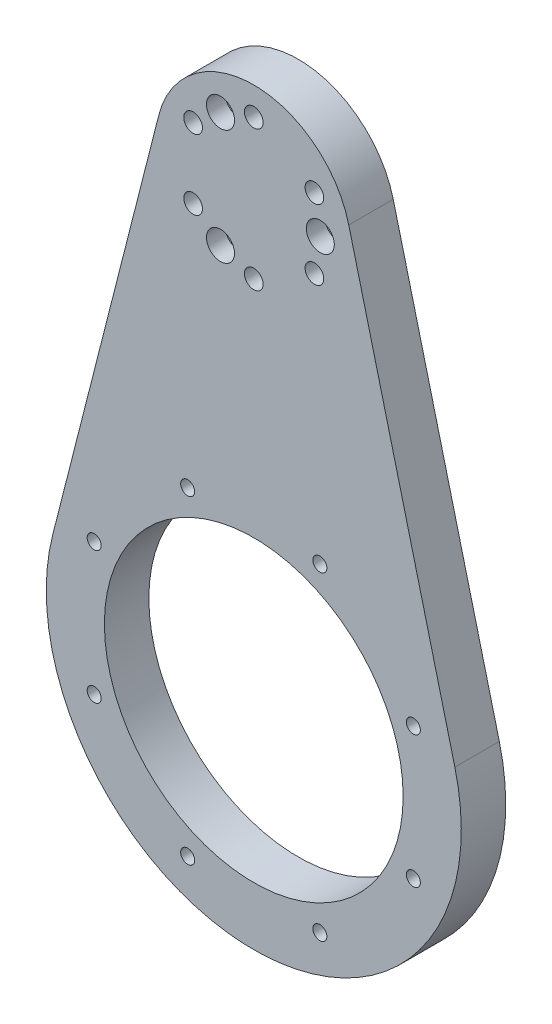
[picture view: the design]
ISO-10303-21;
HEADER;
FILE_DESCRIPTION(('STEP AP214'),'2;1');
FILE_NAME('part.step','',(''),(''),'','','');
FILE_SCHEMA(('AUTOMOTIVE_DESIGN { 1 0 10303 214 1 1 1 1 }'));
ENDSEC;
DATA;
#1=APPLICATION_CONTEXT('core data for automotive mechanical design processes');
#2=APPLICATION_PROTOCOL_DEFINITION('international standard','automotive_design',2000,#1);
#3=PRODUCT_CONTEXT('',#1,'mechanical');
#4=PRODUCT('Part','Part','',(#3));
#5=PRODUCT_RELATED_PRODUCT_CATEGORY('part','',(#4));
#6=PRODUCT_DEFINITION_FORMATION('','',#4);
#7=PRODUCT_DEFINITION_CONTEXT('part definition',#1,'design');
#8=PRODUCT_DEFINITION('design','',#6,#7);
#9=PRODUCT_DEFINITION_SHAPE('','',#8);
#10=(LENGTH_UNIT() NAMED_UNIT(*) SI_UNIT(.MILLI.,.METRE.));
#11=(NAMED_UNIT(*) PLANE_ANGLE_UNIT() SI_UNIT($,.RADIAN.));
#12=(NAMED_UNIT(*) SI_UNIT($,.STERADIAN.) SOLID_ANGLE_UNIT());
#13=UNCERTAINTY_MEASURE_WITH_UNIT(LENGTH_MEASURE(1.E-05),#10,'distance_accuracy_value','');
#14=(GEOMETRIC_REPRESENTATION_CONTEXT(3) GLOBAL_UNCERTAINTY_ASSIGNED_CONTEXT((#13)) GLOBAL_UNIT_ASSIGNED_CONTEXT((#10,
#11,#12)) REPRESENTATION_CONTEXT('',''));
#15=CARTESIAN_POINT('',(0.,0.,0.));
#16=DIRECTION('',(0.,0.,1.));
#17=DIRECTION('',(1.,0.,0.));
#18=AXIS2_PLACEMENT_3D('',#15,#16,#17);
#19=CARTESIAN_POINT('',(0.,-95.,9.525));
#20=DIRECTION('',(0.,0.,1.));
#21=DIRECTION('',(1.,0.,0.));
#22=AXIS2_PLACEMENT_3D('',#19,#20,#21);
#23=PLANE('',#22);
#24=CARTESIAN_POINT('',(14.25,-1.50920942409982E-13,9.525));
#25=DIRECTION('',(0.,0.,1.));
#26=DIRECTION('',(1.,0.,0.));
#27=AXIS2_PLACEMENT_3D('',#24,#25,#26);
#28=CIRCLE('',#27,3.);
#29=CARTESIAN_POINT('',(11.25,-1.50920942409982E-13,9.525));
#30=VERTEX_POINT('',#29);
#31=EDGE_CURVE('E155',#30,#30,#28,.T.);
#32=ORIENTED_EDGE('',*,*,#31,.F.);
#33=EDGE_LOOP('',(#32));
#34=FACE_BOUND('',#33,.T.);
#35=CARTESIAN_POINT('',(-12.9903810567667,-7.49999999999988,9.525));
#36=DIRECTION('',(0.,0.,1.));
#37=DIRECTION('',(1.,0.,0.));
#38=AXIS2_PLACEMENT_3D('',#35,#36,#37);
#39=CIRCLE('',#38,2.);
#40=CARTESIAN_POINT('',(-14.9903810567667,-7.49999999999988,9.525));
#41=VERTEX_POINT('',#40);
#42=EDGE_CURVE('E168',#41,#41,#39,.T.);
#43=ORIENTED_EDGE('',*,*,#42,.F.);
#44=EDGE_LOOP('',(#43));
#45=FACE_BOUND('',#44,.T.);
#46=CARTESIAN_POINT('',(12.9903810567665,-7.50000000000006,9.525));
#47=DIRECTION('',(0.,0.,1.));
#48=DIRECTION('',(1.,0.,0.));
#49=AXIS2_PLACEMENT_3D('',#46,#47,#48);
#50=CIRCLE('',#49,2.);
#51=CARTESIAN_POINT('',(10.9903810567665,-7.50000000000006,9.525));
#52=VERTEX_POINT('',#51);
#53=EDGE_CURVE('E188',#52,#52,#50,.T.);
#54=ORIENTED_EDGE('',*,*,#53,.F.);
#55=EDGE_LOOP('',(#54));
#56=FACE_BOUND('',#55,.T.);
#57=CARTESIAN_POINT('',(-7.12499999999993,12.3408620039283,9.525));
#58=DIRECTION('',(0.,0.,1.));
#59=DIRECTION('',(1.,0.,0.));
#60=AXIS2_PLACEMENT_3D('',#57,#58,#59);
#61=CIRCLE('',#60,3.);
#62=CARTESIAN_POINT('',(-10.1249999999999,12.3408620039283,9.525));
#63=VERTEX_POINT('',#62);
#64=EDGE_CURVE('E196',#63,#63,#61,.T.);
#65=ORIENTED_EDGE('',*,*,#64,.F.);
#66=EDGE_LOOP('',(#65));
#67=FACE_BOUND('',#66,.T.);
#68=CARTESIAN_POINT('',(34.1835427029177,-109.159286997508,9.525));
#69=DIRECTION('',(0.,0.,1.));
#70=DIRECTION('',(1.,0.,0.));
#71=AXIS2_PLACEMENT_3D('',#68,#69,#70);
#72=CIRCLE('',#71,1.49999999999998);
#73=CARTESIAN_POINT('',(32.6835427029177,-109.159286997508,9.525));
#74=VERTEX_POINT('',#73);
#75=EDGE_CURVE('E212',#74,#74,#72,.T.);
#76=ORIENTED_EDGE('',*,*,#75,.F.);
#77=EDGE_LOOP('',(#76));
#78=FACE_BOUND('',#77,.T.);
#79=CARTESIAN_POINT('',(14.1592869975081,-60.8164572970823,9.525));
#80=DIRECTION('',(0.,0.,1.));
#81=DIRECTION('',(1.,0.,0.));
#82=AXIS2_PLACEMENT_3D('',#79,#80,#81);
#83=CIRCLE('',#82,1.5);
#84=CARTESIAN_POINT('',(12.6592869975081,-60.8164572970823,9.525));
#85=VERTEX_POINT('',#84);
#86=EDGE_CURVE('E226',#85,#85,#83,.T.);
#87=ORIENTED_EDGE('',*,*,#86,.F.);
#88=EDGE_LOOP('',(#87));
#89=FACE_BOUND('',#88,.T.);
#90=CARTESIAN_POINT('',(-34.1835427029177,-80.8407130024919,9.525));
#91=DIRECTION('',(0.,0.,1.));
#92=DIRECTION('',(1.,0.,0.));
#93=AXIS2_PLACEMENT_3D('',#90,#91,#92);
#94=CIRCLE('',#93,1.5);
#95=CARTESIAN_POINT('',(-35.6835427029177,-80.8407130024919,9.525));
#96=VERTEX_POINT('',#95);
#97=EDGE_CURVE('E248',#96,#96,#94,.T.);
#98=ORIENTED_EDGE('',*,*,#97,.F.);
#99=EDGE_LOOP('',(#98));
#100=FACE_BOUND('',#99,.T.);
#101=CARTESIAN_POINT('',(0.,15.,9.525));
#102=DIRECTION('',(0.,0.,1.));
#103=DIRECTION('',(1.,0.,0.));
#104=AXIS2_PLACEMENT_3D('',#101,#102,#103);
#105=CIRCLE('',#104,2.);
#106=CARTESIAN_POINT('',(-2.,15.,9.525));
#107=VERTEX_POINT('',#106);
#108=EDGE_CURVE('E265',#107,#107,#105,.T.);
#109=ORIENTED_EDGE('',*,*,#108,.F.);
#110=EDGE_LOOP('',(#109));
#111=FACE_BOUND('',#110,.T.);
#112=CARTESIAN_POINT('',(0.,-95.,9.525));
#113=DIRECTION('',(0.,0.,1.));
#114=DIRECTION('',(1.,0.,0.));
#115=AXIS2_PLACEMENT_3D('',#112,#113,#114);
#116=CIRCLE('',#115,32.);
#117=CARTESIAN_POINT('',(-32.,-95.,9.525));
#118=VERTEX_POINT('',#117);
#119=EDGE_CURVE('E125',#118,#118,#116,.T.);
#120=ORIENTED_EDGE('',*,*,#119,.F.);
#121=EDGE_LOOP('',(#120));
#122=FACE_BOUND('',#121,.T.);
#123=CARTESIAN_POINT('',(0.,-95.,9.525));
#124=DIRECTION('',(0.,0.,1.));
#125=DIRECTION('',(1.,0.,0.));
#126=AXIS2_PLACEMENT_3D('',#123,#124,#125);
#127=CIRCLE('',#126,44.45);
#128=CARTESIAN_POINT('',(-43.074526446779,-84.0278684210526,9.525));
#129=VERTEX_POINT('',#128);
#130=CARTESIAN_POINT('',(43.074526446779,-84.0278684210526,9.525));
#131=VERTEX_POINT('',#130);
#132=EDGE_CURVE('E97',#129,#131,#127,.T.);
#133=ORIENTED_EDGE('',*,*,#132,.T.);
#134=DIRECTION('',(-0.246842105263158,0.969055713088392,0.));
#135=VECTOR('',#134,1.);
#136=CARTESIAN_POINT('',(43.074526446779,-84.0278684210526,9.525));
#137=LINE('',#136,#135);
#138=CARTESIAN_POINT('',(20.3501699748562,5.18368421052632,9.525));
#139=VERTEX_POINT('',#138);
#140=EDGE_CURVE('E94',#131,#139,#137,.T.);
#141=ORIENTED_EDGE('',*,*,#140,.T.);
#142=CARTESIAN_POINT('',(0.,0.,9.525));
#143=DIRECTION('',(0.,0.,1.));
#144=DIRECTION('',(1.,0.,0.));
#145=AXIS2_PLACEMENT_3D('',#142,#143,#144);
#146=CIRCLE('',#145,21.);
#147=CARTESIAN_POINT('',(-20.3501699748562,5.18368421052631,9.525));
#148=VERTEX_POINT('',#147);
#149=EDGE_CURVE('E100',#139,#148,#146,.T.);
#150=ORIENTED_EDGE('',*,*,#149,.T.);
#151=DIRECTION('',(-0.246842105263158,-0.969055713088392,0.));
#152=VECTOR('',#151,1.);
#153=CARTESIAN_POINT('',(-43.074526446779,-84.0278684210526,9.525));
#154=LINE('',#153,#152);
#155=EDGE_CURVE('E62',#148,#129,#154,.T.);
#156=ORIENTED_EDGE('',*,*,#155,.T.);
#157=EDGE_LOOP('',(#133,#141,#150,#156));
#158=FACE_BOUND('',#157,.T.);
#159=CARTESIAN_POINT('',(-14.1592869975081,-129.183542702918,9.525));
#160=DIRECTION('',(0.,0.,1.));
#161=DIRECTION('',(1.,0.,0.));
#162=AXIS2_PLACEMENT_3D('',#159,#160,#161);
#163=CIRCLE('',#162,1.5);
#164=CARTESIAN_POINT('',(-15.6592869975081,-129.183542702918,9.525));
#165=VERTEX_POINT('',#164);
#166=EDGE_CURVE('E269',#165,#165,#163,.T.);
#167=ORIENTED_EDGE('',*,*,#166,.F.);
#168=EDGE_LOOP('',(#167));
#169=FACE_BOUND('',#168,.T.);
#170=CARTESIAN_POINT('',(-34.1835427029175,-109.159286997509,9.525));
#171=DIRECTION('',(0.,0.,1.));
#172=DIRECTION('',(1.,0.,0.));
#173=AXIS2_PLACEMENT_3D('',#170,#171,#172);
#174=CIRCLE('',#173,1.5);
#175=CARTESIAN_POINT('',(-35.6835427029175,-109.159286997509,9.525));
#176=VERTEX_POINT('',#175);
#177=EDGE_CURVE('E255',#176,#176,#174,.T.);
#178=ORIENTED_EDGE('',*,*,#177,.F.);
#179=EDGE_LOOP('',(#178));
#180=FACE_BOUND('',#179,.T.);
#181=CARTESIAN_POINT('',(-14.1592869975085,-60.8164572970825,9.525));
#182=DIRECTION('',(0.,0.,1.));
#183=DIRECTION('',(1.,0.,0.));
#184=AXIS2_PLACEMENT_3D('',#181,#182,#183);
#185=CIRCLE('',#184,1.5);
#186=CARTESIAN_POINT('',(-15.6592869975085,-60.8164572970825,9.525));
#187=VERTEX_POINT('',#186);
#188=EDGE_CURVE('E236',#187,#187,#185,.T.);
#189=ORIENTED_EDGE('',*,*,#188,.F.);
#190=EDGE_LOOP('',(#189));
#191=FACE_BOUND('',#190,.T.);
#192=CARTESIAN_POINT('',(34.1835427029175,-80.8407130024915,9.525));
#193=DIRECTION('',(0.,0.,1.));
#194=DIRECTION('',(1.,0.,0.));
#195=AXIS2_PLACEMENT_3D('',#192,#193,#194);
#196=CIRCLE('',#195,1.5);
#197=CARTESIAN_POINT('',(32.6835427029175,-80.8407130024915,9.525));
#198=VERTEX_POINT('',#197);
#199=EDGE_CURVE('E225',#198,#198,#196,.T.);
#200=ORIENTED_EDGE('',*,*,#199,.F.);
#201=EDGE_LOOP('',(#200));
#202=FACE_BOUND('',#201,.T.);
#203=CARTESIAN_POINT('',(14.1592869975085,-129.183542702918,9.525));
#204=DIRECTION('',(0.,0.,1.));
#205=DIRECTION('',(1.,0.,0.));
#206=AXIS2_PLACEMENT_3D('',#203,#204,#205);
#207=CIRCLE('',#206,1.49999999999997);
#208=CARTESIAN_POINT('',(12.6592869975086,-129.183542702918,9.525));
#209=VERTEX_POINT('',#208);
#210=EDGE_CURVE('E206',#209,#209,#207,.T.);
#211=ORIENTED_EDGE('',*,*,#210,.F.);
#212=EDGE_LOOP('',(#211));
#213=FACE_BOUND('',#212,.T.);
#214=CARTESIAN_POINT('',(12.9903810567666,7.49999999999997,9.525));
#215=DIRECTION('',(0.,0.,1.));
#216=DIRECTION('',(1.,0.,0.));
#217=AXIS2_PLACEMENT_3D('',#214,#215,#216);
#218=CIRCLE('',#217,2.);
#219=CARTESIAN_POINT('',(10.9903810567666,7.49999999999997,9.525));
#220=VERTEX_POINT('',#219);
#221=EDGE_CURVE('E192',#220,#220,#218,.T.);
#222=ORIENTED_EDGE('',*,*,#221,.F.);
#223=EDGE_LOOP('',(#222));
#224=FACE_BOUND('',#223,.T.);
#225=CARTESIAN_POINT('',(-1.04744440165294E-13,-15.,9.525));
#226=DIRECTION('',(0.,0.,1.));
#227=DIRECTION('',(1.,0.,0.));
#228=AXIS2_PLACEMENT_3D('',#225,#226,#227);
#229=CIRCLE('',#228,2.);
#230=CARTESIAN_POINT('',(-2.0000000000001,-15.,9.525));
#231=VERTEX_POINT('',#230);
#232=EDGE_CURVE('E176',#231,#231,#229,.T.);
#233=ORIENTED_EDGE('',*,*,#232,.F.);
#234=EDGE_LOOP('',(#233));
#235=FACE_BOUND('',#234,.T.);
#236=CARTESIAN_POINT('',(-12.9903810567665,7.50000000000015,9.525));
#237=DIRECTION('',(0.,0.,1.));
#238=DIRECTION('',(1.,0.,0.));
#239=AXIS2_PLACEMENT_3D('',#236,#237,#238);
#240=CIRCLE('',#239,2.);
#241=CARTESIAN_POINT('',(-14.9903810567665,7.50000000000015,9.525));
#242=VERTEX_POINT('',#241);
#243=EDGE_CURVE('E161',#242,#242,#240,.T.);
#244=ORIENTED_EDGE('',*,*,#243,.F.);
#245=EDGE_LOOP('',(#244));
#246=FACE_BOUND('',#245,.T.);
#247=CARTESIAN_POINT('',(-7.12500000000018,-12.3408620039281,9.525));
#248=DIRECTION('',(0.,0.,1.));
#249=DIRECTION('',(1.,0.,0.));
#250=AXIS2_PLACEMENT_3D('',#247,#248,#249);
#251=CIRCLE('',#250,3.);
#252=CARTESIAN_POINT('',(-10.1250000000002,-12.3408620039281,9.525));
#253=VERTEX_POINT('',#252);
#254=EDGE_CURVE('E156',#253,#253,#251,.T.);
#255=ORIENTED_EDGE('',*,*,#254,.F.);
#256=EDGE_LOOP('',(#255));
#257=FACE_BOUND('',#256,.T.);
#258=ADVANCED_FACE('F44',(#34,#45,#56,#67,#78,#89,#100,#111,#122,#158,#169,#180,#191,#202,#213,
#224,#235,#246,#257),#23,.T.);
#259=CARTESIAN_POINT('',(0.,-95.,0.));
#260=DIRECTION('',(0.,0.,1.));
#261=DIRECTION('',(1.,0.,0.));
#262=AXIS2_PLACEMENT_3D('',#259,#260,#261);
#263=PLANE('',#262);
#264=CARTESIAN_POINT('',(0.,-95.,0.));
#265=DIRECTION('',(0.,0.,1.));
#266=DIRECTION('',(1.,0.,0.));
#267=AXIS2_PLACEMENT_3D('',#264,#265,#266);
#268=CIRCLE('',#267,44.45);
#269=CARTESIAN_POINT('',(-43.074526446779,-84.0278684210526,0.));
#270=VERTEX_POINT('',#269);
#271=CARTESIAN_POINT('',(43.074526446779,-84.0278684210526,0.));
#272=VERTEX_POINT('',#271);
#273=EDGE_CURVE('E117',#270,#272,#268,.T.);
#274=ORIENTED_EDGE('',*,*,#273,.F.);
#275=DIRECTION('',(-0.246842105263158,-0.969055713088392,0.));
#276=VECTOR('',#275,1.);
#277=CARTESIAN_POINT('',(-43.074526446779,-84.0278684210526,0.));
#278=LINE('',#277,#276);
#279=CARTESIAN_POINT('',(-20.3501699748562,5.18368421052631,0.));
#280=VERTEX_POINT('',#279);
#281=EDGE_CURVE('E88',#280,#270,#278,.T.);
#282=ORIENTED_EDGE('',*,*,#281,.F.);
#283=CARTESIAN_POINT('',(0.,0.,0.));
#284=DIRECTION('',(0.,0.,1.));
#285=DIRECTION('',(1.,0.,0.));
#286=AXIS2_PLACEMENT_3D('',#283,#284,#285);
#287=CIRCLE('',#286,21.);
#288=CARTESIAN_POINT('',(20.3501699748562,5.18368421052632,0.));
#289=VERTEX_POINT('',#288);
#290=EDGE_CURVE('E76',#289,#280,#287,.T.);
#291=ORIENTED_EDGE('',*,*,#290,.F.);
#292=DIRECTION('',(-0.246842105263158,0.969055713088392,0.));
#293=VECTOR('',#292,1.);
#294=CARTESIAN_POINT('',(43.074526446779,-84.0278684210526,0.));
#295=LINE('',#294,#293);
#296=EDGE_CURVE('E104',#272,#289,#295,.T.);
#297=ORIENTED_EDGE('',*,*,#296,.F.);
#298=EDGE_LOOP('',(#274,#282,#291,#297));
#299=FACE_BOUND('',#298,.T.);
#300=CARTESIAN_POINT('',(0.,-95.,0.));
#301=DIRECTION('',(0.,0.,1.));
#302=DIRECTION('',(1.,0.,0.));
#303=AXIS2_PLACEMENT_3D('',#300,#301,#302);
#304=CIRCLE('',#303,32.);
#305=CARTESIAN_POINT('',(-32.,-95.,0.));
#306=VERTEX_POINT('',#305);
#307=EDGE_CURVE('E273',#306,#306,#304,.T.);
#308=ORIENTED_EDGE('',*,*,#307,.T.);
#309=EDGE_LOOP('',(#308));
#310=FACE_BOUND('',#309,.T.);
#311=CARTESIAN_POINT('',(-14.1592869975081,-129.183542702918,0.));
#312=DIRECTION('',(0.,0.,1.));
#313=DIRECTION('',(1.,0.,0.));
#314=AXIS2_PLACEMENT_3D('',#311,#312,#313);
#315=CIRCLE('',#314,1.5);
#316=CARTESIAN_POINT('',(-15.6592869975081,-129.183542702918,0.));
#317=VERTEX_POINT('',#316);
#318=EDGE_CURVE('E266',#317,#317,#315,.T.);
#319=ORIENTED_EDGE('',*,*,#318,.T.);
#320=EDGE_LOOP('',(#319));
#321=FACE_BOUND('',#320,.T.);
#322=CARTESIAN_POINT('',(0.,15.,0.));
#323=DIRECTION('',(0.,0.,1.));
#324=DIRECTION('',(1.,0.,0.));
#325=AXIS2_PLACEMENT_3D('',#322,#323,#324);
#326=CIRCLE('',#325,2.);
#327=CARTESIAN_POINT('',(-2.,15.,0.));
#328=VERTEX_POINT('',#327);
#329=EDGE_CURVE('E256',#328,#328,#326,.T.);
#330=ORIENTED_EDGE('',*,*,#329,.T.);
#331=EDGE_LOOP('',(#330));
#332=FACE_BOUND('',#331,.T.);
#333=CARTESIAN_POINT('',(-34.1835427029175,-109.159286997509,0.));
#334=DIRECTION('',(0.,0.,1.));
#335=DIRECTION('',(1.,0.,0.));
#336=AXIS2_PLACEMENT_3D('',#333,#334,#335);
#337=CIRCLE('',#336,1.5);
#338=CARTESIAN_POINT('',(-35.6835427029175,-109.159286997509,0.));
#339=VERTEX_POINT('',#338);
#340=EDGE_CURVE('E249',#339,#339,#337,.T.);
#341=ORIENTED_EDGE('',*,*,#340,.T.);
#342=EDGE_LOOP('',(#341));
#343=FACE_BOUND('',#342,.T.);
#344=CARTESIAN_POINT('',(-34.1835427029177,-80.8407130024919,0.));
#345=DIRECTION('',(0.,0.,1.));
#346=DIRECTION('',(1.,0.,0.));
#347=AXIS2_PLACEMENT_3D('',#344,#345,#346);
#348=CIRCLE('',#347,1.5);
#349=CARTESIAN_POINT('',(-35.6835427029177,-80.8407130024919,0.));
#350=VERTEX_POINT('',#349);
#351=EDGE_CURVE('E244',#350,#350,#348,.T.);
#352=ORIENTED_EDGE('',*,*,#351,.T.);
#353=EDGE_LOOP('',(#352));
#354=FACE_BOUND('',#353,.T.);
#355=CARTESIAN_POINT('',(-14.1592869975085,-60.8164572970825,0.));
#356=DIRECTION('',(0.,0.,1.));
#357=DIRECTION('',(1.,0.,0.));
#358=AXIS2_PLACEMENT_3D('',#355,#356,#357);
#359=CIRCLE('',#358,1.5);
#360=CARTESIAN_POINT('',(-15.6592869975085,-60.8164572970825,0.));
#361=VERTEX_POINT('',#360);
#362=EDGE_CURVE('E232',#361,#361,#359,.T.);
#363=ORIENTED_EDGE('',*,*,#362,.T.);
#364=EDGE_LOOP('',(#363));
#365=FACE_BOUND('',#364,.T.);
#366=CARTESIAN_POINT('',(14.1592869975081,-60.8164572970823,0.));
#367=DIRECTION('',(0.,0.,1.));
#368=DIRECTION('',(1.,0.,0.));
#369=AXIS2_PLACEMENT_3D('',#366,#367,#368);
#370=CIRCLE('',#369,1.5);
#371=CARTESIAN_POINT('',(12.6592869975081,-60.8164572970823,0.));
#372=VERTEX_POINT('',#371);
#373=EDGE_CURVE('E228',#372,#372,#370,.T.);
#374=ORIENTED_EDGE('',*,*,#373,.T.);
#375=EDGE_LOOP('',(#374));
#376=FACE_BOUND('',#375,.T.);
#377=CARTESIAN_POINT('',(34.1835427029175,-80.8407130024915,0.));
#378=DIRECTION('',(0.,0.,1.));
#379=DIRECTION('',(1.,0.,0.));
#380=AXIS2_PLACEMENT_3D('',#377,#378,#379);
#381=CIRCLE('',#380,1.5);
#382=CARTESIAN_POINT('',(32.6835427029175,-80.8407130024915,0.));
#383=VERTEX_POINT('',#382);
#384=EDGE_CURVE('E217',#383,#383,#381,.T.);
#385=ORIENTED_EDGE('',*,*,#384,.T.);
#386=EDGE_LOOP('',(#385));
#387=FACE_BOUND('',#386,.T.);
#388=CARTESIAN_POINT('',(34.1835427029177,-109.159286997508,0.));
#389=DIRECTION('',(0.,0.,1.));
#390=DIRECTION('',(1.,0.,0.));
#391=AXIS2_PLACEMENT_3D('',#388,#389,#390);
#392=CIRCLE('',#391,1.49999999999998);
#393=CARTESIAN_POINT('',(32.6835427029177,-109.159286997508,0.));
#394=VERTEX_POINT('',#393);
#395=EDGE_CURVE('E209',#394,#394,#392,.T.);
#396=ORIENTED_EDGE('',*,*,#395,.T.);
#397=EDGE_LOOP('',(#396));
#398=FACE_BOUND('',#397,.T.);
#399=CARTESIAN_POINT('',(14.1592869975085,-129.183542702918,0.));
#400=DIRECTION('',(0.,0.,1.));
#401=DIRECTION('',(1.,0.,0.));
#402=AXIS2_PLACEMENT_3D('',#399,#400,#401);
#403=CIRCLE('',#402,1.49999999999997);
#404=CARTESIAN_POINT('',(12.6592869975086,-129.183542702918,0.));
#405=VERTEX_POINT('',#404);
#406=EDGE_CURVE('E202',#405,#405,#403,.T.);
#407=ORIENTED_EDGE('',*,*,#406,.T.);
#408=EDGE_LOOP('',(#407));
#409=FACE_BOUND('',#408,.T.);
#410=CARTESIAN_POINT('',(12.9903810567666,7.49999999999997,0.));
#411=DIRECTION('',(0.,0.,1.));
#412=DIRECTION('',(1.,0.,0.));
#413=AXIS2_PLACEMENT_3D('',#410,#411,#412);
#414=CIRCLE('',#413,2.);
#415=CARTESIAN_POINT('',(10.9903810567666,7.49999999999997,0.));
#416=VERTEX_POINT('',#415);
#417=EDGE_CURVE('E186',#416,#416,#414,.T.);
#418=ORIENTED_EDGE('',*,*,#417,.T.);
#419=EDGE_LOOP('',(#418));
#420=FACE_BOUND('',#419,.T.);
#421=CARTESIAN_POINT('',(12.9903810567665,-7.50000000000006,0.));
#422=DIRECTION('',(0.,0.,1.));
#423=DIRECTION('',(1.,0.,0.));
#424=AXIS2_PLACEMENT_3D('',#421,#422,#423);
#425=CIRCLE('',#424,2.);
#426=CARTESIAN_POINT('',(10.9903810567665,-7.50000000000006,0.));
#427=VERTEX_POINT('',#426);
#428=EDGE_CURVE('E185',#427,#427,#425,.T.);
#429=ORIENTED_EDGE('',*,*,#428,.T.);
#430=EDGE_LOOP('',(#429));
#431=FACE_BOUND('',#430,.T.);
#432=CARTESIAN_POINT('',(-1.04744440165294E-13,-15.,0.));
#433=DIRECTION('',(0.,0.,1.));
#434=DIRECTION('',(1.,0.,0.));
#435=AXIS2_PLACEMENT_3D('',#432,#433,#434);
#436=CIRCLE('',#435,2.);
#437=CARTESIAN_POINT('',(-2.0000000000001,-15.,0.));
#438=VERTEX_POINT('',#437);
#439=EDGE_CURVE('E175',#438,#438,#436,.T.);
#440=ORIENTED_EDGE('',*,*,#439,.T.);
#441=EDGE_LOOP('',(#440));
#442=FACE_BOUND('',#441,.T.);
#443=CARTESIAN_POINT('',(-12.9903810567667,-7.49999999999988,0.));
#444=DIRECTION('',(0.,0.,1.));
#445=DIRECTION('',(1.,0.,0.));
#446=AXIS2_PLACEMENT_3D('',#443,#444,#445);
#447=CIRCLE('',#446,2.);
#448=CARTESIAN_POINT('',(-14.9903810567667,-7.49999999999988,0.));
#449=VERTEX_POINT('',#448);
#450=EDGE_CURVE('E169',#449,#449,#447,.T.);
#451=ORIENTED_EDGE('',*,*,#450,.T.);
#452=EDGE_LOOP('',(#451));
#453=FACE_BOUND('',#452,.T.);
#454=CARTESIAN_POINT('',(-12.9903810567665,7.50000000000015,0.));
#455=DIRECTION('',(0.,0.,1.));
#456=DIRECTION('',(1.,0.,0.));
#457=AXIS2_PLACEMENT_3D('',#454,#455,#456);
#458=CIRCLE('',#457,2.);
#459=CARTESIAN_POINT('',(-14.9903810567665,7.50000000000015,0.));
#460=VERTEX_POINT('',#459);
#461=EDGE_CURVE('E154',#460,#460,#458,.T.);
#462=ORIENTED_EDGE('',*,*,#461,.T.);
#463=EDGE_LOOP('',(#462));
#464=FACE_BOUND('',#463,.T.);
#465=ADVANCED_FACE('F288',(#299,#310,#321,#332,#343,#354,#365,#376,#387,#398,#409,#420,#431,
#442,#453,#464),#263,.F.);
#466=CARTESIAN_POINT('',(0.,-95.,9.525));
#467=DIRECTION('',(0.,0.,-1.));
#468=DIRECTION('',(-1.,0.,0.));
#469=AXIS2_PLACEMENT_3D('',#466,#467,#468);
#470=CYLINDRICAL_SURFACE('',#469,44.45);
#471=ORIENTED_EDGE('',*,*,#273,.T.);
#472=DIRECTION('',(0.,0.,-1.));
#473=VECTOR('',#472,1.);
#474=CARTESIAN_POINT('',(43.074526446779,-84.0278684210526,9.525));
#475=LINE('',#474,#473);
#476=EDGE_CURVE('E110',#131,#272,#475,.T.);
#477=ORIENTED_EDGE('',*,*,#476,.F.);
#478=ORIENTED_EDGE('',*,*,#132,.F.);
#479=DIRECTION('',(0.,0.,-1.));
#480=VECTOR('',#479,1.);
#481=CARTESIAN_POINT('',(-43.074526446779,-84.0278684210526,9.525));
#482=LINE('',#481,#480);
#483=EDGE_CURVE('E111',#129,#270,#482,.T.);
#484=ORIENTED_EDGE('',*,*,#483,.T.);
#485=EDGE_LOOP('',(#471,#477,#478,#484));
#486=FACE_BOUND('',#485,.T.);
#487=ADVANCED_FACE('F50',(#486),#470,.T.);
#488=CARTESIAN_POINT('',(43.074526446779,-84.0278684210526,9.525));
#489=DIRECTION('',(-0.969055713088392,-0.246842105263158,0.));
#490=DIRECTION('',(0.246842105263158,-0.969055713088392,0.));
#491=AXIS2_PLACEMENT_3D('',#488,#489,#490);
#492=PLANE('',#491);
#493=ORIENTED_EDGE('',*,*,#296,.T.);
#494=DIRECTION('',(0.,0.,-1.));
#495=VECTOR('',#494,1.);
#496=CARTESIAN_POINT('',(20.3501699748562,5.18368421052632,9.525));
#497=LINE('',#496,#495);
#498=EDGE_CURVE('E103',#139,#289,#497,.T.);
#499=ORIENTED_EDGE('',*,*,#498,.F.);
#500=ORIENTED_EDGE('',*,*,#140,.F.);
#501=ORIENTED_EDGE('',*,*,#476,.T.);
#502=EDGE_LOOP('',(#493,#499,#500,#501));
#503=FACE_BOUND('',#502,.T.);
#504=ADVANCED_FACE('F102',(#503),#492,.F.);
#505=CARTESIAN_POINT('',(0.,0.,9.525));
#506=DIRECTION('',(0.,0.,-1.));
#507=DIRECTION('',(-1.,0.,0.));
#508=AXIS2_PLACEMENT_3D('',#505,#506,#507);
#509=CYLINDRICAL_SURFACE('',#508,21.);
#510=ORIENTED_EDGE('',*,*,#290,.T.);
#511=DIRECTION('',(0.,0.,-1.));
#512=VECTOR('',#511,1.);
#513=CARTESIAN_POINT('',(-20.3501699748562,5.18368421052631,9.525));
#514=LINE('',#513,#512);
#515=EDGE_CURVE('E107',#148,#280,#514,.T.);
#516=ORIENTED_EDGE('',*,*,#515,.F.);
#517=ORIENTED_EDGE('',*,*,#149,.F.);
#518=ORIENTED_EDGE('',*,*,#498,.T.);
#519=EDGE_LOOP('',(#510,#516,#517,#518));
#520=FACE_BOUND('',#519,.T.);
#521=ADVANCED_FACE('F109',(#520),#509,.T.);
#522=CARTESIAN_POINT('',(-43.074526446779,-84.0278684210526,9.525));
#523=DIRECTION('',(0.969055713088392,-0.246842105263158,0.));
#524=DIRECTION('',(0.246842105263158,0.969055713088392,0.));
#525=AXIS2_PLACEMENT_3D('',#522,#523,#524);
#526=PLANE('',#525);
#527=ORIENTED_EDGE('',*,*,#281,.T.);
#528=ORIENTED_EDGE('',*,*,#483,.F.);
#529=ORIENTED_EDGE('',*,*,#155,.F.);
#530=ORIENTED_EDGE('',*,*,#515,.T.);
#531=EDGE_LOOP('',(#527,#528,#529,#530));
#532=FACE_BOUND('',#531,.T.);
#533=ADVANCED_FACE('F295',(#532),#526,.F.);
#534=CARTESIAN_POINT('',(0.,-95.,9.525));
#535=DIRECTION('',(0.,0.,-1.));
#536=DIRECTION('',(-1.,0.,0.));
#537=AXIS2_PLACEMENT_3D('',#534,#535,#536);
#538=CYLINDRICAL_SURFACE('',#537,32.);
#539=CARTESIAN_POINT('',(-32.,-95.,9.525));
#540=CARTESIAN_POINT('',(-32.,-95.,9.42578125));
#541=CARTESIAN_POINT('',(-32.,-95.,9.3265625));
#542=CARTESIAN_POINT('',(-32.,-95.,9.128125));
#543=CARTESIAN_POINT('',(-32.,-95.,9.02890625));
#544=CARTESIAN_POINT('',(-32.,-95.,8.83046875));
#545=CARTESIAN_POINT('',(-32.,-95.,8.73125));
#546=CARTESIAN_POINT('',(-32.,-95.,8.5328125));
#547=CARTESIAN_POINT('',(-32.,-95.,8.43359375));
#548=CARTESIAN_POINT('',(-32.,-95.,8.23515625));
#549=CARTESIAN_POINT('',(-32.,-95.,8.1359375));
#550=CARTESIAN_POINT('',(-32.,-95.,7.9375));
#551=CARTESIAN_POINT('',(-32.,-95.,7.83828125));
#552=CARTESIAN_POINT('',(-32.,-95.,7.63984375));
#553=CARTESIAN_POINT('',(-32.,-95.,7.540625));
#554=CARTESIAN_POINT('',(-32.,-95.,7.3421875));
#555=CARTESIAN_POINT('',(-32.,-95.,7.24296875));
#556=CARTESIAN_POINT('',(-32.,-95.,7.04453125));
#557=CARTESIAN_POINT('',(-32.,-95.,6.9453125));
#558=CARTESIAN_POINT('',(-32.,-95.,6.746875));
#559=CARTESIAN_POINT('',(-32.,-95.,6.64765625));
#560=CARTESIAN_POINT('',(-32.,-95.,6.44921875));
#561=CARTESIAN_POINT('',(-32.,-95.,6.35));
#562=CARTESIAN_POINT('',(-32.,-95.,6.1515625));
#563=CARTESIAN_POINT('',(-32.,-95.,6.05234375));
#564=CARTESIAN_POINT('',(-32.,-95.,5.85390625));
#565=CARTESIAN_POINT('',(-32.,-95.,5.7546875));
#566=CARTESIAN_POINT('',(-32.,-95.,5.55625));
#567=CARTESIAN_POINT('',(-32.,-95.,5.45703125));
#568=CARTESIAN_POINT('',(-32.,-95.,5.25859375));
#569=CARTESIAN_POINT('',(-32.,-95.,5.159375));
#570=CARTESIAN_POINT('',(-32.,-95.,4.9609375));
#571=CARTESIAN_POINT('',(-32.,-95.,4.86171875));
#572=CARTESIAN_POINT('',(-32.,-95.,4.66328125));
#573=CARTESIAN_POINT('',(-32.,-95.,4.5640625));
#574=CARTESIAN_POINT('',(-32.,-95.,4.365625));
#575=CARTESIAN_POINT('',(-32.,-95.,4.26640625));
#576=CARTESIAN_POINT('',(-32.,-95.,4.06796875));
#577=CARTESIAN_POINT('',(-32.,-95.,3.96875));
#578=CARTESIAN_POINT('',(-32.,-95.,3.7703125));
#579=CARTESIAN_POINT('',(-32.,-95.,3.67109375));
#580=CARTESIAN_POINT('',(-32.,-95.,3.47265625));
#581=CARTESIAN_POINT('',(-32.,-95.,3.3734375));
#582=CARTESIAN_POINT('',(-32.,-95.,3.175));
#583=CARTESIAN_POINT('',(-32.,-95.,3.07578125));
#584=CARTESIAN_POINT('',(-32.,-95.,2.87734375));
#585=CARTESIAN_POINT('',(-32.,-95.,2.778125));
#586=CARTESIAN_POINT('',(-32.,-95.,2.5796875));
#587=CARTESIAN_POINT('',(-32.,-95.,2.48046875));
#588=CARTESIAN_POINT('',(-32.,-95.,2.28203125));
#589=CARTESIAN_POINT('',(-32.,-95.,2.1828125));
#590=CARTESIAN_POINT('',(-32.,-95.,1.984375));
#591=CARTESIAN_POINT('',(-32.,-95.,1.88515625));
#592=CARTESIAN_POINT('',(-32.,-95.,1.68671875));
#593=CARTESIAN_POINT('',(-32.,-95.,1.5875));
#594=CARTESIAN_POINT('',(-32.,-95.,1.3890625));
#595=CARTESIAN_POINT('',(-32.,-95.,1.28984375));
#596=CARTESIAN_POINT('',(-32.,-95.,1.09140625));
#597=CARTESIAN_POINT('',(-32.,-95.,0.992187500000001));
#598=CARTESIAN_POINT('',(-32.,-95.,0.793750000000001));
#599=CARTESIAN_POINT('',(-32.,-95.,0.69453125));
#600=CARTESIAN_POINT('',(-32.,-95.,0.49609375));
#601=CARTESIAN_POINT('',(-32.,-95.,0.396875));
#602=CARTESIAN_POINT('',(-32.,-95.,0.1984375));
#603=CARTESIAN_POINT('',(-32.,-95.,0.0992187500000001));
#604=CARTESIAN_POINT('',(-32.,-95.,0.));
#605=B_SPLINE_CURVE_WITH_KNOTS('',3,(#539,#540,#541,#542,#543,#544,#545,#546,#547,#548,#549,
#550,#551,#552,#553,#554,#555,#556,#557,#558,#559,#560,#561,#562,#563,#564,#565,#566,#567,#568,
#569,#570,#571,#572,#573,#574,#575,#576,#577,#578,#579,#580,#581,#582,#583,#584,#585,#586,#587,
#588,#589,#590,#591,#592,#593,#594,#595,#596,#597,#598,#599,#600,#601,#602,#603,#604),
.UNSPECIFIED.,.F.,.F.,(4,2,2,2,2,2,2,2,2,2,2,2,2,2,2,2,2,2,2,2,2,2,2,2,2,2,2,2,2,2,2,2,4),(0.,
0.297656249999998,0.595312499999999,0.892968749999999,1.190625,1.48828125,1.7859375,2.08359375,
2.38125,2.67890625,2.9765625,3.27421875,3.571875,3.86953125,4.1671875,4.46484375,4.7625,
5.06015625,5.3578125,5.65546875,5.953125,6.25078125,6.5484375,6.84609375,7.14375,7.44140625,
7.7390625,8.03671875,8.334375,8.63203125,8.9296875,9.22734375,9.525),.UNSPECIFIED.);
#606=EDGE_CURVE('BSEAM287',#118,#306,#605,.T.);
#607=ORIENTED_EDGE('',*,*,#119,.T.);
#608=ORIENTED_EDGE('',*,*,#307,.F.);
#609=ORIENTED_EDGE('',*,*,#606,.T.);
#610=ORIENTED_EDGE('',*,*,#606,.F.);
#611=EDGE_LOOP('',(#607,#609,#608,#610));
#612=FACE_BOUND('',#611,.T.);
#613=ADVANCED_FACE('F287',(#612),#538,.F.);
#614=CARTESIAN_POINT('',(-14.1592869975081,-129.183542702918,9.525));
#615=DIRECTION('',(0.,0.,-1.));
#616=DIRECTION('',(-1.,0.,0.));
#617=AXIS2_PLACEMENT_3D('',#614,#615,#616);
#618=CYLINDRICAL_SURFACE('',#617,1.5);
#619=CARTESIAN_POINT('',(-15.6592869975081,-129.183542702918,9.525));
#620=CARTESIAN_POINT('',(-15.6592869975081,-129.183542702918,9.42578125));
#621=CARTESIAN_POINT('',(-15.6592869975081,-129.183542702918,9.3265625));
#622=CARTESIAN_POINT('',(-15.6592869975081,-129.183542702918,9.128125));
#623=CARTESIAN_POINT('',(-15.6592869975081,-129.183542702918,9.02890625));
#624=CARTESIAN_POINT('',(-15.6592869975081,-129.183542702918,8.83046875));
#625=CARTESIAN_POINT('',(-15.6592869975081,-129.183542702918,8.73125));
#626=CARTESIAN_POINT('',(-15.6592869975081,-129.183542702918,8.5328125));
#627=CARTESIAN_POINT('',(-15.6592869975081,-129.183542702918,8.43359375));
#628=CARTESIAN_POINT('',(-15.6592869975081,-129.183542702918,8.23515625));
#629=CARTESIAN_POINT('',(-15.6592869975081,-129.183542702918,8.1359375));
#630=CARTESIAN_POINT('',(-15.6592869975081,-129.183542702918,7.9375));
#631=CARTESIAN_POINT('',(-15.6592869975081,-129.183542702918,7.83828125));
#632=CARTESIAN_POINT('',(-15.6592869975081,-129.183542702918,7.63984375));
#633=CARTESIAN_POINT('',(-15.6592869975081,-129.183542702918,7.540625));
#634=CARTESIAN_POINT('',(-15.6592869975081,-129.183542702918,7.3421875));
#635=CARTESIAN_POINT('',(-15.6592869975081,-129.183542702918,7.24296875));
#636=CARTESIAN_POINT('',(-15.6592869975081,-129.183542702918,7.04453125));
#637=CARTESIAN_POINT('',(-15.6592869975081,-129.183542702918,6.9453125));
#638=CARTESIAN_POINT('',(-15.6592869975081,-129.183542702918,6.746875));
#639=CARTESIAN_POINT('',(-15.6592869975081,-129.183542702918,6.64765625));
#640=CARTESIAN_POINT('',(-15.6592869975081,-129.183542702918,6.44921875));
#641=CARTESIAN_POINT('',(-15.6592869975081,-129.183542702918,6.35));
#642=CARTESIAN_POINT('',(-15.6592869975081,-129.183542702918,6.1515625));
#643=CARTESIAN_POINT('',(-15.6592869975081,-129.183542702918,6.05234375));
#644=CARTESIAN_POINT('',(-15.6592869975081,-129.183542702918,5.85390625));
#645=CARTESIAN_POINT('',(-15.6592869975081,-129.183542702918,5.7546875));
#646=CARTESIAN_POINT('',(-15.6592869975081,-129.183542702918,5.55625));
#647=CARTESIAN_POINT('',(-15.6592869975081,-129.183542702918,5.45703125));
#648=CARTESIAN_POINT('',(-15.6592869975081,-129.183542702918,5.25859375));
#649=CARTESIAN_POINT('',(-15.6592869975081,-129.183542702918,5.159375));
#650=CARTESIAN_POINT('',(-15.6592869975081,-129.183542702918,4.9609375));
#651=CARTESIAN_POINT('',(-15.6592869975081,-129.183542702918,4.86171875));
#652=CARTESIAN_POINT('',(-15.6592869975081,-129.183542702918,4.66328125));
#653=CARTESIAN_POINT('',(-15.6592869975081,-129.183542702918,4.5640625));
#654=CARTESIAN_POINT('',(-15.6592869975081,-129.183542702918,4.365625));
#655=CARTESIAN_POINT('',(-15.6592869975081,-129.183542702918,4.26640625));
#656=CARTESIAN_POINT('',(-15.6592869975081,-129.183542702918,4.06796875));
#657=CARTESIAN_POINT('',(-15.6592869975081,-129.183542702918,3.96875));
#658=CARTESIAN_POINT('',(-15.6592869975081,-129.183542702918,3.7703125));
#659=CARTESIAN_POINT('',(-15.6592869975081,-129.183542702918,3.67109375));
#660=CARTESIAN_POINT('',(-15.6592869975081,-129.183542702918,3.47265625));
#661=CARTESIAN_POINT('',(-15.6592869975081,-129.183542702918,3.3734375));
#662=CARTESIAN_POINT('',(-15.6592869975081,-129.183542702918,3.175));
#663=CARTESIAN_POINT('',(-15.6592869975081,-129.183542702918,3.07578125));
#664=CARTESIAN_POINT('',(-15.6592869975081,-129.183542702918,2.87734375));
#665=CARTESIAN_POINT('',(-15.6592869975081,-129.183542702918,2.778125));
#666=CARTESIAN_POINT('',(-15.6592869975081,-129.183542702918,2.5796875));
#667=CARTESIAN_POINT('',(-15.6592869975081,-129.183542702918,2.48046875));
#668=CARTESIAN_POINT('',(-15.6592869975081,-129.183542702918,2.28203125));
#669=CARTESIAN_POINT('',(-15.6592869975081,-129.183542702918,2.1828125));
#670=CARTESIAN_POINT('',(-15.6592869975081,-129.183542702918,1.984375));
#671=CARTESIAN_POINT('',(-15.6592869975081,-129.183542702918,1.88515625));
#672=CARTESIAN_POINT('',(-15.6592869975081,-129.183542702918,1.68671875));
#673=CARTESIAN_POINT('',(-15.6592869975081,-129.183542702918,1.5875));
#674=CARTESIAN_POINT('',(-15.6592869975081,-129.183542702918,1.3890625));
#675=CARTESIAN_POINT('',(-15.6592869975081,-129.183542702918,1.28984375));
#676=CARTESIAN_POINT('',(-15.6592869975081,-129.183542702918,1.09140625));
#677=CARTESIAN_POINT('',(-15.6592869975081,-129.183542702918,0.992187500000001));
#678=CARTESIAN_POINT('',(-15.6592869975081,-129.183542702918,0.793750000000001));
#679=CARTESIAN_POINT('',(-15.6592869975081,-129.183542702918,0.69453125));
#680=CARTESIAN_POINT('',(-15.6592869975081,-129.183542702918,0.49609375));
#681=CARTESIAN_POINT('',(-15.6592869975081,-129.183542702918,0.396875));
#682=CARTESIAN_POINT('',(-15.6592869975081,-129.183542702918,0.1984375));
#683=CARTESIAN_POINT('',(-15.6592869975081,-129.183542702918,0.0992187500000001));
#684=CARTESIAN_POINT('',(-15.6592869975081,-129.183542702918,0.));
#685=B_SPLINE_CURVE_WITH_KNOTS('',3,(#619,#620,#621,#622,#623,#624,#625,#626,#627,#628,#629,
#630,#631,#632,#633,#634,#635,#636,#637,#638,#639,#640,#641,#642,#643,#644,#645,#646,#647,#648,
#649,#650,#651,#652,#653,#654,#655,#656,#657,#658,#659,#660,#661,#662,#663,#664,#665,#666,#667,
#668,#669,#670,#671,#672,#673,#674,#675,#676,#677,#678,#679,#680,#681,#682,#683,#684),
.UNSPECIFIED.,.F.,.F.,(4,2,2,2,2,2,2,2,2,2,2,2,2,2,2,2,2,2,2,2,2,2,2,2,2,2,2,2,2,2,2,2,4),(0.,
0.29765625,0.5953125,0.892968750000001,1.190625,1.48828125,1.7859375,2.08359375,2.38125,
2.67890625,2.9765625,3.27421875,3.571875,3.86953125,4.1671875,4.46484375,4.7625,5.06015625,
5.3578125,5.65546875,5.953125,6.25078125,6.5484375,6.84609375,7.14375,7.44140625,7.7390625,
8.03671875,8.334375,8.63203125,8.9296875,9.22734375,9.525),.UNSPECIFIED.);
#686=EDGE_CURVE('BSEAM292',#165,#317,#685,.T.);
#687=ORIENTED_EDGE('',*,*,#166,.T.);
#688=ORIENTED_EDGE('',*,*,#318,.F.);
#689=ORIENTED_EDGE('',*,*,#686,.T.);
#690=ORIENTED_EDGE('',*,*,#686,.F.);
#691=EDGE_LOOP('',(#687,#689,#688,#690));
#692=FACE_BOUND('',#691,.T.);
#693=ADVANCED_FACE('F292',(#692),#618,.F.);
#694=CARTESIAN_POINT('',(0.,15.,9.525));
#695=DIRECTION('',(0.,0.,-1.));
#696=DIRECTION('',(-1.,0.,0.));
#697=AXIS2_PLACEMENT_3D('',#694,#695,#696);
#698=CYLINDRICAL_SURFACE('',#697,2.);
#699=CARTESIAN_POINT('',(-2.,15.,9.525));
#700=CARTESIAN_POINT('',(-2.,15.,9.42578125));
#701=CARTESIAN_POINT('',(-2.,15.,9.3265625));
#702=CARTESIAN_POINT('',(-2.,15.,9.128125));
#703=CARTESIAN_POINT('',(-2.,15.,9.02890625));
#704=CARTESIAN_POINT('',(-2.,15.,8.83046875));
#705=CARTESIAN_POINT('',(-2.,15.,8.73125));
#706=CARTESIAN_POINT('',(-2.,15.,8.5328125));
#707=CARTESIAN_POINT('',(-2.,15.,8.43359375));
#708=CARTESIAN_POINT('',(-2.,15.,8.23515625));
#709=CARTESIAN_POINT('',(-2.,15.,8.1359375));
#710=CARTESIAN_POINT('',(-2.,15.,7.9375));
#711=CARTESIAN_POINT('',(-2.,15.,7.83828125));
#712=CARTESIAN_POINT('',(-2.,15.,7.63984375));
#713=CARTESIAN_POINT('',(-2.,15.,7.540625));
#714=CARTESIAN_POINT('',(-2.,15.,7.3421875));
#715=CARTESIAN_POINT('',(-2.,15.,7.24296875));
#716=CARTESIAN_POINT('',(-2.,15.,7.04453125));
#717=CARTESIAN_POINT('',(-2.,15.,6.9453125));
#718=CARTESIAN_POINT('',(-2.,15.,6.746875));
#719=CARTESIAN_POINT('',(-2.,15.,6.64765625));
#720=CARTESIAN_POINT('',(-2.,15.,6.44921875));
#721=CARTESIAN_POINT('',(-2.,15.,6.35));
#722=CARTESIAN_POINT('',(-2.,15.,6.1515625));
#723=CARTESIAN_POINT('',(-2.,15.,6.05234375));
#724=CARTESIAN_POINT('',(-2.,15.,5.85390625));
#725=CARTESIAN_POINT('',(-2.,15.,5.7546875));
#726=CARTESIAN_POINT('',(-2.,15.,5.55625));
#727=CARTESIAN_POINT('',(-2.,15.,5.45703125));
#728=CARTESIAN_POINT('',(-2.,15.,5.25859375));
#729=CARTESIAN_POINT('',(-2.,15.,5.159375));
#730=CARTESIAN_POINT('',(-2.,15.,4.9609375));
#731=CARTESIAN_POINT('',(-2.,15.,4.86171875));
#732=CARTESIAN_POINT('',(-2.,15.,4.66328125));
#733=CARTESIAN_POINT('',(-2.,15.,4.5640625));
#734=CARTESIAN_POINT('',(-2.,15.,4.365625));
#735=CARTESIAN_POINT('',(-2.,15.,4.26640625));
#736=CARTESIAN_POINT('',(-2.,15.,4.06796875));
#737=CARTESIAN_POINT('',(-2.,15.,3.96875));
#738=CARTESIAN_POINT('',(-2.,15.,3.7703125));
#739=CARTESIAN_POINT('',(-2.,15.,3.67109375));
#740=CARTESIAN_POINT('',(-2.,15.,3.47265625));
#741=CARTESIAN_POINT('',(-2.,15.,3.3734375));
#742=CARTESIAN_POINT('',(-2.,15.,3.175));
#743=CARTESIAN_POINT('',(-2.,15.,3.07578125));
#744=CARTESIAN_POINT('',(-2.,15.,2.87734375));
#745=CARTESIAN_POINT('',(-2.,15.,2.778125));
#746=CARTESIAN_POINT('',(-2.,15.,2.5796875));
#747=CARTESIAN_POINT('',(-2.,15.,2.48046875));
#748=CARTESIAN_POINT('',(-2.,15.,2.28203125));
#749=CARTESIAN_POINT('',(-2.,15.,2.1828125));
#750=CARTESIAN_POINT('',(-2.,15.,1.984375));
#751=CARTESIAN_POINT('',(-2.,15.,1.88515625));
#752=CARTESIAN_POINT('',(-2.,15.,1.68671875));
#753=CARTESIAN_POINT('',(-2.,15.,1.5875));
#754=CARTESIAN_POINT('',(-2.,15.,1.3890625));
#755=CARTESIAN_POINT('',(-2.,15.,1.28984375));
#756=CARTESIAN_POINT('',(-2.,15.,1.09140625));
#757=CARTESIAN_POINT('',(-2.,15.,0.992187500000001));
#758=CARTESIAN_POINT('',(-2.,15.,0.793750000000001));
#759=CARTESIAN_POINT('',(-2.,15.,0.69453125));
#760=CARTESIAN_POINT('',(-2.,15.,0.49609375));
#761=CARTESIAN_POINT('',(-2.,15.,0.396875));
#762=CARTESIAN_POINT('',(-2.,15.,0.1984375));
#763=CARTESIAN_POINT('',(-2.,15.,0.0992187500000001));
#764=CARTESIAN_POINT('',(-2.,15.,0.));
#765=B_SPLINE_CURVE_WITH_KNOTS('',3,(#699,#700,#701,#702,#703,#704,#705,#706,#707,#708,#709,
#710,#711,#712,#713,#714,#715,#716,#717,#718,#719,#720,#721,#722,#723,#724,#725,#726,#727,#728,
#729,#730,#731,#732,#733,#734,#735,#736,#737,#738,#739,#740,#741,#742,#743,#744,#745,#746,#747,
#748,#749,#750,#751,#752,#753,#754,#755,#756,#757,#758,#759,#760,#761,#762,#763,#764),
.UNSPECIFIED.,.F.,.F.,(4,2,2,2,2,2,2,2,2,2,2,2,2,2,2,2,2,2,2,2,2,2,2,2,2,2,2,2,2,2,2,2,4),(0.,
0.297656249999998,0.595312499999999,0.892968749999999,1.190625,1.48828125,1.7859375,2.08359375,
2.38125,2.67890625,2.9765625,3.27421875,3.571875,3.86953125,4.1671875,4.46484375,4.7625,
5.06015625,5.3578125,5.65546875,5.953125,6.25078125,6.5484375,6.84609375,7.14375,7.44140625,
7.7390625,8.03671875,8.334375,8.63203125,8.9296875,9.22734375,9.525),.UNSPECIFIED.);
#766=EDGE_CURVE('BSEAM300',#107,#328,#765,.T.);
#767=ORIENTED_EDGE('',*,*,#108,.T.);
#768=ORIENTED_EDGE('',*,*,#329,.F.);
#769=ORIENTED_EDGE('',*,*,#766,.T.);
#770=ORIENTED_EDGE('',*,*,#766,.F.);
#771=EDGE_LOOP('',(#767,#769,#768,#770));
#772=FACE_BOUND('',#771,.T.);
#773=ADVANCED_FACE('F300',(#772),#698,.F.);
#774=CARTESIAN_POINT('',(-34.1835427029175,-109.159286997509,9.525));
#775=DIRECTION('',(0.,0.,-1.));
#776=DIRECTION('',(-1.,0.,0.));
#777=AXIS2_PLACEMENT_3D('',#774,#775,#776);
#778=CYLINDRICAL_SURFACE('',#777,1.5);
#779=CARTESIAN_POINT('',(-35.6835427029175,-109.159286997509,9.525));
#780=CARTESIAN_POINT('',(-35.6835427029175,-109.159286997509,9.42578125));
#781=CARTESIAN_POINT('',(-35.6835427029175,-109.159286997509,9.3265625));
#782=CARTESIAN_POINT('',(-35.6835427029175,-109.159286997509,9.128125));
#783=CARTESIAN_POINT('',(-35.6835427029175,-109.159286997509,9.02890625));
#784=CARTESIAN_POINT('',(-35.6835427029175,-109.159286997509,8.83046875));
#785=CARTESIAN_POINT('',(-35.6835427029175,-109.159286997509,8.73125));
#786=CARTESIAN_POINT('',(-35.6835427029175,-109.159286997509,8.5328125));
#787=CARTESIAN_POINT('',(-35.6835427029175,-109.159286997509,8.43359375));
#788=CARTESIAN_POINT('',(-35.6835427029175,-109.159286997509,8.23515625));
#789=CARTESIAN_POINT('',(-35.6835427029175,-109.159286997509,8.1359375));
#790=CARTESIAN_POINT('',(-35.6835427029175,-109.159286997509,7.9375));
#791=CARTESIAN_POINT('',(-35.6835427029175,-109.159286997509,7.83828125));
#792=CARTESIAN_POINT('',(-35.6835427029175,-109.159286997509,7.63984375));
#793=CARTESIAN_POINT('',(-35.6835427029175,-109.159286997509,7.540625));
#794=CARTESIAN_POINT('',(-35.6835427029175,-109.159286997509,7.3421875));
#795=CARTESIAN_POINT('',(-35.6835427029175,-109.159286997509,7.24296875));
#796=CARTESIAN_POINT('',(-35.6835427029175,-109.159286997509,7.04453125));
#797=CARTESIAN_POINT('',(-35.6835427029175,-109.159286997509,6.9453125));
#798=CARTESIAN_POINT('',(-35.6835427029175,-109.159286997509,6.746875));
#799=CARTESIAN_POINT('',(-35.6835427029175,-109.159286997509,6.64765625));
#800=CARTESIAN_POINT('',(-35.6835427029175,-109.159286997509,6.44921875));
#801=CARTESIAN_POINT('',(-35.6835427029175,-109.159286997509,6.35));
#802=CARTESIAN_POINT('',(-35.6835427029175,-109.159286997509,6.1515625));
#803=CARTESIAN_POINT('',(-35.6835427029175,-109.159286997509,6.05234375));
#804=CARTESIAN_POINT('',(-35.6835427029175,-109.159286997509,5.85390625));
#805=CARTESIAN_POINT('',(-35.6835427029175,-109.159286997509,5.7546875));
#806=CARTESIAN_POINT('',(-35.6835427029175,-109.159286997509,5.55625));
#807=CARTESIAN_POINT('',(-35.6835427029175,-109.159286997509,5.45703125));
#808=CARTESIAN_POINT('',(-35.6835427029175,-109.159286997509,5.25859375));
#809=CARTESIAN_POINT('',(-35.6835427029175,-109.159286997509,5.159375));
#810=CARTESIAN_POINT('',(-35.6835427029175,-109.159286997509,4.9609375));
#811=CARTESIAN_POINT('',(-35.6835427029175,-109.159286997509,4.86171875));
#812=CARTESIAN_POINT('',(-35.6835427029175,-109.159286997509,4.66328125));
#813=CARTESIAN_POINT('',(-35.6835427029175,-109.159286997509,4.5640625));
#814=CARTESIAN_POINT('',(-35.6835427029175,-109.159286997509,4.365625));
#815=CARTESIAN_POINT('',(-35.6835427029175,-109.159286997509,4.26640625));
#816=CARTESIAN_POINT('',(-35.6835427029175,-109.159286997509,4.06796875));
#817=CARTESIAN_POINT('',(-35.6835427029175,-109.159286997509,3.96875));
#818=CARTESIAN_POINT('',(-35.6835427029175,-109.159286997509,3.7703125));
#819=CARTESIAN_POINT('',(-35.6835427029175,-109.159286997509,3.67109375));
#820=CARTESIAN_POINT('',(-35.6835427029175,-109.159286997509,3.47265625));
#821=CARTESIAN_POINT('',(-35.6835427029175,-109.159286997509,3.3734375));
#822=CARTESIAN_POINT('',(-35.6835427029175,-109.159286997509,3.175));
#823=CARTESIAN_POINT('',(-35.6835427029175,-109.159286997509,3.07578125));
#824=CARTESIAN_POINT('',(-35.6835427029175,-109.159286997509,2.87734375));
#825=CARTESIAN_POINT('',(-35.6835427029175,-109.159286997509,2.778125));
#826=CARTESIAN_POINT('',(-35.6835427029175,-109.159286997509,2.5796875));
#827=CARTESIAN_POINT('',(-35.6835427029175,-109.159286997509,2.48046875));
#828=CARTESIAN_POINT('',(-35.6835427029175,-109.159286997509,2.28203125));
#829=CARTESIAN_POINT('',(-35.6835427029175,-109.159286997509,2.1828125));
#830=CARTESIAN_POINT('',(-35.6835427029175,-109.159286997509,1.984375));
#831=CARTESIAN_POINT('',(-35.6835427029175,-109.159286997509,1.88515625));
#832=CARTESIAN_POINT('',(-35.6835427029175,-109.159286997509,1.68671875));
#833=CARTESIAN_POINT('',(-35.6835427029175,-109.159286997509,1.5875));
#834=CARTESIAN_POINT('',(-35.6835427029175,-109.159286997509,1.3890625));
#835=CARTESIAN_POINT('',(-35.6835427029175,-109.159286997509,1.28984375));
#836=CARTESIAN_POINT('',(-35.6835427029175,-109.159286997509,1.09140625));
#837=CARTESIAN_POINT('',(-35.6835427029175,-109.159286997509,0.992187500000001));
#838=CARTESIAN_POINT('',(-35.6835427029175,-109.159286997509,0.793750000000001));
#839=CARTESIAN_POINT('',(-35.6835427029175,-109.159286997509,0.69453125));
#840=CARTESIAN_POINT('',(-35.6835427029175,-109.159286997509,0.49609375));
#841=CARTESIAN_POINT('',(-35.6835427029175,-109.159286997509,0.396875));
#842=CARTESIAN_POINT('',(-35.6835427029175,-109.159286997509,0.1984375));
#843=CARTESIAN_POINT('',(-35.6835427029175,-109.159286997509,0.0992187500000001));
#844=CARTESIAN_POINT('',(-35.6835427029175,-109.159286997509,0.));
#845=B_SPLINE_CURVE_WITH_KNOTS('',3,(#779,#780,#781,#782,#783,#784,#785,#786,#787,#788,#789,
#790,#791,#792,#793,#794,#795,#796,#797,#798,#799,#800,#801,#802,#803,#804,#805,#806,#807,#808,
#809,#810,#811,#812,#813,#814,#815,#816,#817,#818,#819,#820,#821,#822,#823,#824,#825,#826,#827,
#828,#829,#830,#831,#832,#833,#834,#835,#836,#837,#838,#839,#840,#841,#842,#843,#844),
.UNSPECIFIED.,.F.,.F.,(4,2,2,2,2,2,2,2,2,2,2,2,2,2,2,2,2,2,2,2,2,2,2,2,2,2,2,2,2,2,2,2,4),(0.,
0.29765625,0.5953125,0.892968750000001,1.190625,1.48828125,1.7859375,2.08359375,2.38125,
2.67890625,2.9765625,3.27421875,3.571875,3.86953125,4.1671875,4.46484375,4.7625,5.06015625,
5.3578125,5.65546875,5.953125,6.25078125,6.5484375,6.84609375,7.14375,7.44140625,7.7390625,
8.03671875,8.334375,8.63203125,8.9296875,9.22734375,9.525),.UNSPECIFIED.);
#846=EDGE_CURVE('BSEAM362',#176,#339,#845,.T.);
#847=ORIENTED_EDGE('',*,*,#177,.T.);
#848=ORIENTED_EDGE('',*,*,#340,.F.);
#849=ORIENTED_EDGE('',*,*,#846,.T.);
#850=ORIENTED_EDGE('',*,*,#846,.F.);
#851=EDGE_LOOP('',(#847,#849,#848,#850));
#852=FACE_BOUND('',#851,.T.);
#853=ADVANCED_FACE('F362',(#852),#778,.F.);
#854=CARTESIAN_POINT('',(-34.1835427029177,-80.8407130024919,9.525));
#855=DIRECTION('',(0.,0.,-1.));
#856=DIRECTION('',(-1.,0.,0.));
#857=AXIS2_PLACEMENT_3D('',#854,#855,#856);
#858=CYLINDRICAL_SURFACE('',#857,1.5);
#859=CARTESIAN_POINT('',(-35.6835427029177,-80.8407130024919,9.525));
#860=CARTESIAN_POINT('',(-35.6835427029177,-80.8407130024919,9.42578125));
#861=CARTESIAN_POINT('',(-35.6835427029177,-80.8407130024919,9.3265625));
#862=CARTESIAN_POINT('',(-35.6835427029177,-80.8407130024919,9.128125));
#863=CARTESIAN_POINT('',(-35.6835427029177,-80.8407130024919,9.02890625));
#864=CARTESIAN_POINT('',(-35.6835427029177,-80.8407130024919,8.83046875));
#865=CARTESIAN_POINT('',(-35.6835427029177,-80.8407130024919,8.73125));
#866=CARTESIAN_POINT('',(-35.6835427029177,-80.8407130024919,8.5328125));
#867=CARTESIAN_POINT('',(-35.6835427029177,-80.8407130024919,8.43359375));
#868=CARTESIAN_POINT('',(-35.6835427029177,-80.8407130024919,8.23515625));
#869=CARTESIAN_POINT('',(-35.6835427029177,-80.8407130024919,8.1359375));
#870=CARTESIAN_POINT('',(-35.6835427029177,-80.8407130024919,7.9375));
#871=CARTESIAN_POINT('',(-35.6835427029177,-80.8407130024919,7.83828125));
#872=CARTESIAN_POINT('',(-35.6835427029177,-80.8407130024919,7.63984375));
#873=CARTESIAN_POINT('',(-35.6835427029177,-80.8407130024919,7.540625));
#874=CARTESIAN_POINT('',(-35.6835427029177,-80.8407130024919,7.3421875));
#875=CARTESIAN_POINT('',(-35.6835427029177,-80.8407130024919,7.24296875));
#876=CARTESIAN_POINT('',(-35.6835427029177,-80.8407130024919,7.04453125));
#877=CARTESIAN_POINT('',(-35.6835427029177,-80.8407130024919,6.9453125));
#878=CARTESIAN_POINT('',(-35.6835427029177,-80.8407130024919,6.746875));
#879=CARTESIAN_POINT('',(-35.6835427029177,-80.8407130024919,6.64765625));
#880=CARTESIAN_POINT('',(-35.6835427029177,-80.8407130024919,6.44921875));
#881=CARTESIAN_POINT('',(-35.6835427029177,-80.8407130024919,6.35));
#882=CARTESIAN_POINT('',(-35.6835427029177,-80.8407130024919,6.1515625));
#883=CARTESIAN_POINT('',(-35.6835427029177,-80.8407130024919,6.05234375));
#884=CARTESIAN_POINT('',(-35.6835427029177,-80.8407130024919,5.85390625));
#885=CARTESIAN_POINT('',(-35.6835427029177,-80.8407130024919,5.7546875));
#886=CARTESIAN_POINT('',(-35.6835427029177,-80.8407130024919,5.55625));
#887=CARTESIAN_POINT('',(-35.6835427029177,-80.8407130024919,5.45703125));
#888=CARTESIAN_POINT('',(-35.6835427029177,-80.8407130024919,5.25859375));
#889=CARTESIAN_POINT('',(-35.6835427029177,-80.8407130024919,5.159375));
#890=CARTESIAN_POINT('',(-35.6835427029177,-80.8407130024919,4.9609375));
#891=CARTESIAN_POINT('',(-35.6835427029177,-80.8407130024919,4.86171875));
#892=CARTESIAN_POINT('',(-35.6835427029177,-80.8407130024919,4.66328125));
#893=CARTESIAN_POINT('',(-35.6835427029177,-80.8407130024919,4.5640625));
#894=CARTESIAN_POINT('',(-35.6835427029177,-80.8407130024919,4.365625));
#895=CARTESIAN_POINT('',(-35.6835427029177,-80.8407130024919,4.26640625));
#896=CARTESIAN_POINT('',(-35.6835427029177,-80.8407130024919,4.06796875));
#897=CARTESIAN_POINT('',(-35.6835427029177,-80.8407130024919,3.96875));
#898=CARTESIAN_POINT('',(-35.6835427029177,-80.8407130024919,3.7703125));
#899=CARTESIAN_POINT('',(-35.6835427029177,-80.8407130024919,3.67109375));
#900=CARTESIAN_POINT('',(-35.6835427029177,-80.8407130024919,3.47265625));
#901=CARTESIAN_POINT('',(-35.6835427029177,-80.8407130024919,3.3734375));
#902=CARTESIAN_POINT('',(-35.6835427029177,-80.8407130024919,3.175));
#903=CARTESIAN_POINT('',(-35.6835427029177,-80.8407130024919,3.07578125));
#904=CARTESIAN_POINT('',(-35.6835427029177,-80.8407130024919,2.87734375));
#905=CARTESIAN_POINT('',(-35.6835427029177,-80.8407130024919,2.778125));
#906=CARTESIAN_POINT('',(-35.6835427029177,-80.8407130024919,2.5796875));
#907=CARTESIAN_POINT('',(-35.6835427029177,-80.8407130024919,2.48046875));
#908=CARTESIAN_POINT('',(-35.6835427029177,-80.8407130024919,2.28203125));
#909=CARTESIAN_POINT('',(-35.6835427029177,-80.8407130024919,2.1828125));
#910=CARTESIAN_POINT('',(-35.6835427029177,-80.8407130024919,1.984375));
#911=CARTESIAN_POINT('',(-35.6835427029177,-80.8407130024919,1.88515625));
#912=CARTESIAN_POINT('',(-35.6835427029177,-80.8407130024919,1.68671875));
#913=CARTESIAN_POINT('',(-35.6835427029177,-80.8407130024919,1.5875));
#914=CARTESIAN_POINT('',(-35.6835427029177,-80.8407130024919,1.3890625));
#915=CARTESIAN_POINT('',(-35.6835427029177,-80.8407130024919,1.28984375));
#916=CARTESIAN_POINT('',(-35.6835427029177,-80.8407130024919,1.09140625));
#917=CARTESIAN_POINT('',(-35.6835427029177,-80.8407130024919,0.992187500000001));
#918=CARTESIAN_POINT('',(-35.6835427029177,-80.8407130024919,0.793750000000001));
#919=CARTESIAN_POINT('',(-35.6835427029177,-80.8407130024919,0.69453125));
#920=CARTESIAN_POINT('',(-35.6835427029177,-80.8407130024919,0.49609375));
#921=CARTESIAN_POINT('',(-35.6835427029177,-80.8407130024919,0.396875));
#922=CARTESIAN_POINT('',(-35.6835427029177,-80.8407130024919,0.1984375));
#923=CARTESIAN_POINT('',(-35.6835427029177,-80.8407130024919,0.0992187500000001));
#924=CARTESIAN_POINT('',(-35.6835427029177,-80.8407130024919,0.));
#925=B_SPLINE_CURVE_WITH_KNOTS('',3,(#859,#860,#861,#862,#863,#864,#865,#866,#867,#868,#869,
#870,#871,#872,#873,#874,#875,#876,#877,#878,#879,#880,#881,#882,#883,#884,#885,#886,#887,#888,
#889,#890,#891,#892,#893,#894,#895,#896,#897,#898,#899,#900,#901,#902,#903,#904,#905,#906,#907,
#908,#909,#910,#911,#912,#913,#914,#915,#916,#917,#918,#919,#920,#921,#922,#923,#924),
.UNSPECIFIED.,.F.,.F.,(4,2,2,2,2,2,2,2,2,2,2,2,2,2,2,2,2,2,2,2,2,2,2,2,2,2,2,2,2,2,2,2,4),(0.,
0.29765625,0.5953125,0.892968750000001,1.190625,1.48828125,1.7859375,2.08359375,2.38125,
2.67890625,2.9765625,3.27421875,3.571875,3.86953125,4.1671875,4.46484375,4.7625,5.06015625,
5.3578125,5.65546875,5.953125,6.25078125,6.5484375,6.84609375,7.14375,7.44140625,7.7390625,
8.03671875,8.334375,8.63203125,8.9296875,9.22734375,9.525),.UNSPECIFIED.);
#926=EDGE_CURVE('BSEAM375',#96,#350,#925,.T.);
#927=ORIENTED_EDGE('',*,*,#97,.T.);
#928=ORIENTED_EDGE('',*,*,#351,.F.);
#929=ORIENTED_EDGE('',*,*,#926,.T.);
#930=ORIENTED_EDGE('',*,*,#926,.F.);
#931=EDGE_LOOP('',(#927,#929,#928,#930));
#932=FACE_BOUND('',#931,.T.);
#933=ADVANCED_FACE('F375',(#932),#858,.F.);
#934=CARTESIAN_POINT('',(-14.1592869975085,-60.8164572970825,9.525));
#935=DIRECTION('',(0.,0.,-1.));
#936=DIRECTION('',(-1.,0.,0.));
#937=AXIS2_PLACEMENT_3D('',#934,#935,#936);
#938=CYLINDRICAL_SURFACE('',#937,1.5);
#939=CARTESIAN_POINT('',(-15.6592869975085,-60.8164572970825,9.525));
#940=CARTESIAN_POINT('',(-15.6592869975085,-60.8164572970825,9.42578125));
#941=CARTESIAN_POINT('',(-15.6592869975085,-60.8164572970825,9.3265625));
#942=CARTESIAN_POINT('',(-15.6592869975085,-60.8164572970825,9.128125));
#943=CARTESIAN_POINT('',(-15.6592869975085,-60.8164572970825,9.02890625));
#944=CARTESIAN_POINT('',(-15.6592869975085,-60.8164572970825,8.83046875));
#945=CARTESIAN_POINT('',(-15.6592869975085,-60.8164572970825,8.73125));
#946=CARTESIAN_POINT('',(-15.6592869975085,-60.8164572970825,8.5328125));
#947=CARTESIAN_POINT('',(-15.6592869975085,-60.8164572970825,8.43359375));
#948=CARTESIAN_POINT('',(-15.6592869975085,-60.8164572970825,8.23515625));
#949=CARTESIAN_POINT('',(-15.6592869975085,-60.8164572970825,8.1359375));
#950=CARTESIAN_POINT('',(-15.6592869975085,-60.8164572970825,7.9375));
#951=CARTESIAN_POINT('',(-15.6592869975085,-60.8164572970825,7.83828125));
#952=CARTESIAN_POINT('',(-15.6592869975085,-60.8164572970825,7.63984375));
#953=CARTESIAN_POINT('',(-15.6592869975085,-60.8164572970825,7.540625));
#954=CARTESIAN_POINT('',(-15.6592869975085,-60.8164572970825,7.3421875));
#955=CARTESIAN_POINT('',(-15.6592869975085,-60.8164572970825,7.24296875));
#956=CARTESIAN_POINT('',(-15.6592869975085,-60.8164572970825,7.04453125));
#957=CARTESIAN_POINT('',(-15.6592869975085,-60.8164572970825,6.9453125));
#958=CARTESIAN_POINT('',(-15.6592869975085,-60.8164572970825,6.746875));
#959=CARTESIAN_POINT('',(-15.6592869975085,-60.8164572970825,6.64765625));
#960=CARTESIAN_POINT('',(-15.6592869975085,-60.8164572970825,6.44921875));
#961=CARTESIAN_POINT('',(-15.6592869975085,-60.8164572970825,6.35));
#962=CARTESIAN_POINT('',(-15.6592869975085,-60.8164572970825,6.1515625));
#963=CARTESIAN_POINT('',(-15.6592869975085,-60.8164572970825,6.05234375));
#964=CARTESIAN_POINT('',(-15.6592869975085,-60.8164572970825,5.85390625));
#965=CARTESIAN_POINT('',(-15.6592869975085,-60.8164572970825,5.7546875));
#966=CARTESIAN_POINT('',(-15.6592869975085,-60.8164572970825,5.55625));
#967=CARTESIAN_POINT('',(-15.6592869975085,-60.8164572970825,5.45703125));
#968=CARTESIAN_POINT('',(-15.6592869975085,-60.8164572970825,5.25859375));
#969=CARTESIAN_POINT('',(-15.6592869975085,-60.8164572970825,5.159375));
#970=CARTESIAN_POINT('',(-15.6592869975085,-60.8164572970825,4.9609375));
#971=CARTESIAN_POINT('',(-15.6592869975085,-60.8164572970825,4.86171875));
#972=CARTESIAN_POINT('',(-15.6592869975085,-60.8164572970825,4.66328125));
#973=CARTESIAN_POINT('',(-15.6592869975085,-60.8164572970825,4.5640625));
#974=CARTESIAN_POINT('',(-15.6592869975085,-60.8164572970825,4.365625));
#975=CARTESIAN_POINT('',(-15.6592869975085,-60.8164572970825,4.26640625));
#976=CARTESIAN_POINT('',(-15.6592869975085,-60.8164572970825,4.06796875));
#977=CARTESIAN_POINT('',(-15.6592869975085,-60.8164572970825,3.96875));
#978=CARTESIAN_POINT('',(-15.6592869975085,-60.8164572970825,3.7703125));
#979=CARTESIAN_POINT('',(-15.6592869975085,-60.8164572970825,3.67109375));
#980=CARTESIAN_POINT('',(-15.6592869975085,-60.8164572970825,3.47265625));
#981=CARTESIAN_POINT('',(-15.6592869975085,-60.8164572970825,3.3734375));
#982=CARTESIAN_POINT('',(-15.6592869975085,-60.8164572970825,3.175));
#983=CARTESIAN_POINT('',(-15.6592869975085,-60.8164572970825,3.07578125));
#984=CARTESIAN_POINT('',(-15.6592869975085,-60.8164572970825,2.87734375));
#985=CARTESIAN_POINT('',(-15.6592869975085,-60.8164572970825,2.778125));
#986=CARTESIAN_POINT('',(-15.6592869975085,-60.8164572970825,2.5796875));
#987=CARTESIAN_POINT('',(-15.6592869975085,-60.8164572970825,2.48046875));
#988=CARTESIAN_POINT('',(-15.6592869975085,-60.8164572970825,2.28203125));
#989=CARTESIAN_POINT('',(-15.6592869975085,-60.8164572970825,2.1828125));
#990=CARTESIAN_POINT('',(-15.6592869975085,-60.8164572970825,1.984375));
#991=CARTESIAN_POINT('',(-15.6592869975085,-60.8164572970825,1.88515625));
#992=CARTESIAN_POINT('',(-15.6592869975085,-60.8164572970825,1.68671875));
#993=CARTESIAN_POINT('',(-15.6592869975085,-60.8164572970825,1.5875));
#994=CARTESIAN_POINT('',(-15.6592869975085,-60.8164572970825,1.3890625));
#995=CARTESIAN_POINT('',(-15.6592869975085,-60.8164572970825,1.28984375));
#996=CARTESIAN_POINT('',(-15.6592869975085,-60.8164572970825,1.09140625));
#997=CARTESIAN_POINT('',(-15.6592869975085,-60.8164572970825,0.992187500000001));
#998=CARTESIAN_POINT('',(-15.6592869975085,-60.8164572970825,0.793750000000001));
#999=CARTESIAN_POINT('',(-15.6592869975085,-60.8164572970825,0.69453125));
#1000=CARTESIAN_POINT('',(-15.6592869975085,-60.8164572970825,0.49609375));
#1001=CARTESIAN_POINT('',(-15.6592869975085,-60.8164572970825,0.396875));
#1002=CARTESIAN_POINT('',(-15.6592869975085,-60.8164572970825,0.1984375));
#1003=CARTESIAN_POINT('',(-15.6592869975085,-60.8164572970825,0.0992187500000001));
#1004=CARTESIAN_POINT('',(-15.6592869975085,-60.8164572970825,0.));
#1005=B_SPLINE_CURVE_WITH_KNOTS('',3,(#939,#940,#941,#942,#943,#944,#945,#946,#947,#948,#949,
#950,#951,#952,#953,#954,#955,#956,#957,#958,#959,#960,#961,#962,#963,#964,#965,#966,#967,#968,
#969,#970,#971,#972,#973,#974,#975,#976,#977,#978,#979,#980,#981,#982,#983,#984,#985,#986,#987,
#988,#989,#990,#991,#992,#993,#994,#995,#996,#997,#998,#999,#1000,#1001,#1002,#1003,#1004),
.UNSPECIFIED.,.F.,.F.,(4,2,2,2,2,2,2,2,2,2,2,2,2,2,2,2,2,2,2,2,2,2,2,2,2,2,2,2,2,2,2,2,4),(0.,
0.29765625,0.5953125,0.892968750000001,1.190625,1.48828125,1.7859375,2.08359375,2.38125,
2.67890625,2.9765625,3.27421875,3.571875,3.86953125,4.1671875,4.46484375,4.7625,5.06015625,
5.3578125,5.65546875,5.953125,6.25078125,6.5484375,6.84609375,7.14375,7.44140625,7.7390625,
8.03671875,8.334375,8.63203125,8.9296875,9.22734375,9.525),.UNSPECIFIED.);
#1006=EDGE_CURVE('BSEAM385',#187,#361,#1005,.T.);
#1007=ORIENTED_EDGE('',*,*,#188,.T.);
#1008=ORIENTED_EDGE('',*,*,#362,.F.);
#1009=ORIENTED_EDGE('',*,*,#1006,.T.);
#1010=ORIENTED_EDGE('',*,*,#1006,.F.);
#1011=EDGE_LOOP('',(#1007,#1009,#1008,#1010));
#1012=FACE_BOUND('',#1011,.T.);
#1013=ADVANCED_FACE('F385',(#1012),#938,.F.);
#1014=CARTESIAN_POINT('',(14.1592869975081,-60.8164572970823,9.525));
#1015=DIRECTION('',(0.,0.,-1.));
#1016=DIRECTION('',(-1.,0.,0.));
#1017=AXIS2_PLACEMENT_3D('',#1014,#1015,#1016);
#1018=CYLINDRICAL_SURFACE('',#1017,1.5);
#1019=CARTESIAN_POINT('',(12.6592869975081,-60.8164572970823,9.525));
#1020=CARTESIAN_POINT('',(12.6592869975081,-60.8164572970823,9.42578125));
#1021=CARTESIAN_POINT('',(12.6592869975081,-60.8164572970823,9.3265625));
#1022=CARTESIAN_POINT('',(12.6592869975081,-60.8164572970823,9.128125));
#1023=CARTESIAN_POINT('',(12.6592869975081,-60.8164572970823,9.02890625));
#1024=CARTESIAN_POINT('',(12.6592869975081,-60.8164572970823,8.83046875));
#1025=CARTESIAN_POINT('',(12.6592869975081,-60.8164572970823,8.73125));
#1026=CARTESIAN_POINT('',(12.6592869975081,-60.8164572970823,8.5328125));
#1027=CARTESIAN_POINT('',(12.6592869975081,-60.8164572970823,8.43359375));
#1028=CARTESIAN_POINT('',(12.6592869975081,-60.8164572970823,8.23515625));
#1029=CARTESIAN_POINT('',(12.6592869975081,-60.8164572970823,8.1359375));
#1030=CARTESIAN_POINT('',(12.6592869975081,-60.8164572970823,7.9375));
#1031=CARTESIAN_POINT('',(12.6592869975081,-60.8164572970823,7.83828125));
#1032=CARTESIAN_POINT('',(12.6592869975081,-60.8164572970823,7.63984375));
#1033=CARTESIAN_POINT('',(12.6592869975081,-60.8164572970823,7.540625));
#1034=CARTESIAN_POINT('',(12.6592869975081,-60.8164572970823,7.3421875));
#1035=CARTESIAN_POINT('',(12.6592869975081,-60.8164572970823,7.24296875));
#1036=CARTESIAN_POINT('',(12.6592869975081,-60.8164572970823,7.04453125));
#1037=CARTESIAN_POINT('',(12.6592869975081,-60.8164572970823,6.9453125));
#1038=CARTESIAN_POINT('',(12.6592869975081,-60.8164572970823,6.746875));
#1039=CARTESIAN_POINT('',(12.6592869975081,-60.8164572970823,6.64765625));
#1040=CARTESIAN_POINT('',(12.6592869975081,-60.8164572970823,6.44921875));
#1041=CARTESIAN_POINT('',(12.6592869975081,-60.8164572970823,6.35));
#1042=CARTESIAN_POINT('',(12.6592869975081,-60.8164572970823,6.1515625));
#1043=CARTESIAN_POINT('',(12.6592869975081,-60.8164572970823,6.05234375));
#1044=CARTESIAN_POINT('',(12.6592869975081,-60.8164572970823,5.85390625));
#1045=CARTESIAN_POINT('',(12.6592869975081,-60.8164572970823,5.7546875));
#1046=CARTESIAN_POINT('',(12.6592869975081,-60.8164572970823,5.55625));
#1047=CARTESIAN_POINT('',(12.6592869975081,-60.8164572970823,5.45703125));
#1048=CARTESIAN_POINT('',(12.6592869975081,-60.8164572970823,5.25859375));
#1049=CARTESIAN_POINT('',(12.6592869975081,-60.8164572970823,5.159375));
#1050=CARTESIAN_POINT('',(12.6592869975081,-60.8164572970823,4.9609375));
#1051=CARTESIAN_POINT('',(12.6592869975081,-60.8164572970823,4.86171875));
#1052=CARTESIAN_POINT('',(12.6592869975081,-60.8164572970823,4.66328125));
#1053=CARTESIAN_POINT('',(12.6592869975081,-60.8164572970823,4.5640625));
#1054=CARTESIAN_POINT('',(12.6592869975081,-60.8164572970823,4.365625));
#1055=CARTESIAN_POINT('',(12.6592869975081,-60.8164572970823,4.26640625));
#1056=CARTESIAN_POINT('',(12.6592869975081,-60.8164572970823,4.06796875));
#1057=CARTESIAN_POINT('',(12.6592869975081,-60.8164572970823,3.96875));
#1058=CARTESIAN_POINT('',(12.6592869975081,-60.8164572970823,3.7703125));
#1059=CARTESIAN_POINT('',(12.6592869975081,-60.8164572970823,3.67109375));
#1060=CARTESIAN_POINT('',(12.6592869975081,-60.8164572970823,3.47265625));
#1061=CARTESIAN_POINT('',(12.6592869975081,-60.8164572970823,3.3734375));
#1062=CARTESIAN_POINT('',(12.6592869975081,-60.8164572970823,3.175));
#1063=CARTESIAN_POINT('',(12.6592869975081,-60.8164572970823,3.07578125));
#1064=CARTESIAN_POINT('',(12.6592869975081,-60.8164572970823,2.87734375));
#1065=CARTESIAN_POINT('',(12.6592869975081,-60.8164572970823,2.778125));
#1066=CARTESIAN_POINT('',(12.6592869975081,-60.8164572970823,2.5796875));
#1067=CARTESIAN_POINT('',(12.6592869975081,-60.8164572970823,2.48046875));
#1068=CARTESIAN_POINT('',(12.6592869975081,-60.8164572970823,2.28203125));
#1069=CARTESIAN_POINT('',(12.6592869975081,-60.8164572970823,2.1828125));
#1070=CARTESIAN_POINT('',(12.6592869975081,-60.8164572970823,1.984375));
#1071=CARTESIAN_POINT('',(12.6592869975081,-60.8164572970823,1.88515625));
#1072=CARTESIAN_POINT('',(12.6592869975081,-60.8164572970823,1.68671875));
#1073=CARTESIAN_POINT('',(12.6592869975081,-60.8164572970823,1.5875));
#1074=CARTESIAN_POINT('',(12.6592869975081,-60.8164572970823,1.3890625));
#1075=CARTESIAN_POINT('',(12.6592869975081,-60.8164572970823,1.28984375));
#1076=CARTESIAN_POINT('',(12.6592869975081,-60.8164572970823,1.09140625));
#1077=CARTESIAN_POINT('',(12.6592869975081,-60.8164572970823,0.992187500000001));
#1078=CARTESIAN_POINT('',(12.6592869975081,-60.8164572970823,0.793750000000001));
#1079=CARTESIAN_POINT('',(12.6592869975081,-60.8164572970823,0.69453125));
#1080=CARTESIAN_POINT('',(12.6592869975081,-60.8164572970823,0.49609375));
#1081=CARTESIAN_POINT('',(12.6592869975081,-60.8164572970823,0.396875));
#1082=CARTESIAN_POINT('',(12.6592869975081,-60.8164572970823,0.1984375));
#1083=CARTESIAN_POINT('',(12.6592869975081,-60.8164572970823,0.0992187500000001));
#1084=CARTESIAN_POINT('',(12.6592869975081,-60.8164572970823,0.));
#1085=B_SPLINE_CURVE_WITH_KNOTS('',3,(#1019,#1020,#1021,#1022,#1023,#1024,#1025,#1026,#1027,
#1028,#1029,#1030,#1031,#1032,#1033,#1034,#1035,#1036,#1037,#1038,#1039,#1040,#1041,#1042,#1043,
#1044,#1045,#1046,#1047,#1048,#1049,#1050,#1051,#1052,#1053,#1054,#1055,#1056,#1057,#1058,#1059,
#1060,#1061,#1062,#1063,#1064,#1065,#1066,#1067,#1068,#1069,#1070,#1071,#1072,#1073,#1074,#1075,
#1076,#1077,#1078,#1079,#1080,#1081,#1082,#1083,#1084),.UNSPECIFIED.,.F.,.F.,(4,2,2,2,2,2,2,2,2,
2,2,2,2,2,2,2,2,2,2,2,2,2,2,2,2,2,2,2,2,2,2,2,4),(0.,0.29765625,0.5953125,0.892968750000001,
1.190625,1.48828125,1.7859375,2.08359375,2.38125,2.67890625,2.9765625,3.27421875,3.571875,
3.86953125,4.1671875,4.46484375,4.7625,5.06015625,5.3578125,5.65546875,5.953125,6.25078125,
6.5484375,6.84609375,7.14375,7.44140625,7.7390625,8.03671875,8.334375,8.63203125,8.9296875,
9.22734375,9.525),.UNSPECIFIED.);
#1086=EDGE_CURVE('BSEAM394',#85,#372,#1085,.T.);
#1087=ORIENTED_EDGE('',*,*,#86,.T.);
#1088=ORIENTED_EDGE('',*,*,#373,.F.);
#1089=ORIENTED_EDGE('',*,*,#1086,.T.);
#1090=ORIENTED_EDGE('',*,*,#1086,.F.);
#1091=EDGE_LOOP('',(#1087,#1089,#1088,#1090));
#1092=FACE_BOUND('',#1091,.T.);
#1093=ADVANCED_FACE('F394',(#1092),#1018,.F.);
#1094=CARTESIAN_POINT('',(34.1835427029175,-80.8407130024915,9.525));
#1095=DIRECTION('',(0.,0.,-1.));
#1096=DIRECTION('',(-1.,0.,0.));
#1097=AXIS2_PLACEMENT_3D('',#1094,#1095,#1096);
#1098=CYLINDRICAL_SURFACE('',#1097,1.5);
#1099=CARTESIAN_POINT('',(32.6835427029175,-80.8407130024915,9.525));
#1100=CARTESIAN_POINT('',(32.6835427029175,-80.8407130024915,9.42578125));
#1101=CARTESIAN_POINT('',(32.6835427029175,-80.8407130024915,9.3265625));
#1102=CARTESIAN_POINT('',(32.6835427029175,-80.8407130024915,9.128125));
#1103=CARTESIAN_POINT('',(32.6835427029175,-80.8407130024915,9.02890625));
#1104=CARTESIAN_POINT('',(32.6835427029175,-80.8407130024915,8.83046875));
#1105=CARTESIAN_POINT('',(32.6835427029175,-80.8407130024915,8.73125));
#1106=CARTESIAN_POINT('',(32.6835427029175,-80.8407130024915,8.5328125));
#1107=CARTESIAN_POINT('',(32.6835427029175,-80.8407130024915,8.43359375));
#1108=CARTESIAN_POINT('',(32.6835427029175,-80.8407130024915,8.23515625));
#1109=CARTESIAN_POINT('',(32.6835427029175,-80.8407130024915,8.1359375));
#1110=CARTESIAN_POINT('',(32.6835427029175,-80.8407130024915,7.9375));
#1111=CARTESIAN_POINT('',(32.6835427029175,-80.8407130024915,7.83828125));
#1112=CARTESIAN_POINT('',(32.6835427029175,-80.8407130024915,7.63984375));
#1113=CARTESIAN_POINT('',(32.6835427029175,-80.8407130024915,7.540625));
#1114=CARTESIAN_POINT('',(32.6835427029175,-80.8407130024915,7.3421875));
#1115=CARTESIAN_POINT('',(32.6835427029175,-80.8407130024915,7.24296875));
#1116=CARTESIAN_POINT('',(32.6835427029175,-80.8407130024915,7.04453125));
#1117=CARTESIAN_POINT('',(32.6835427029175,-80.8407130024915,6.9453125));
#1118=CARTESIAN_POINT('',(32.6835427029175,-80.8407130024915,6.746875));
#1119=CARTESIAN_POINT('',(32.6835427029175,-80.8407130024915,6.64765625));
#1120=CARTESIAN_POINT('',(32.6835427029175,-80.8407130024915,6.44921875));
#1121=CARTESIAN_POINT('',(32.6835427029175,-80.8407130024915,6.35));
#1122=CARTESIAN_POINT('',(32.6835427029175,-80.8407130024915,6.1515625));
#1123=CARTESIAN_POINT('',(32.6835427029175,-80.8407130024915,6.05234375));
#1124=CARTESIAN_POINT('',(32.6835427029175,-80.8407130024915,5.85390625));
#1125=CARTESIAN_POINT('',(32.6835427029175,-80.8407130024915,5.7546875));
#1126=CARTESIAN_POINT('',(32.6835427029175,-80.8407130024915,5.55625));
#1127=CARTESIAN_POINT('',(32.6835427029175,-80.8407130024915,5.45703125));
#1128=CARTESIAN_POINT('',(32.6835427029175,-80.8407130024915,5.25859375));
#1129=CARTESIAN_POINT('',(32.6835427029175,-80.8407130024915,5.159375));
#1130=CARTESIAN_POINT('',(32.6835427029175,-80.8407130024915,4.9609375));
#1131=CARTESIAN_POINT('',(32.6835427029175,-80.8407130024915,4.86171875));
#1132=CARTESIAN_POINT('',(32.6835427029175,-80.8407130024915,4.66328125));
#1133=CARTESIAN_POINT('',(32.6835427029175,-80.8407130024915,4.5640625));
#1134=CARTESIAN_POINT('',(32.6835427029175,-80.8407130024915,4.365625));
#1135=CARTESIAN_POINT('',(32.6835427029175,-80.8407130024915,4.26640625));
#1136=CARTESIAN_POINT('',(32.6835427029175,-80.8407130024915,4.06796875));
#1137=CARTESIAN_POINT('',(32.6835427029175,-80.8407130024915,3.96875));
#1138=CARTESIAN_POINT('',(32.6835427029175,-80.8407130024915,3.7703125));
#1139=CARTESIAN_POINT('',(32.6835427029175,-80.8407130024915,3.67109375));
#1140=CARTESIAN_POINT('',(32.6835427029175,-80.8407130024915,3.47265625));
#1141=CARTESIAN_POINT('',(32.6835427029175,-80.8407130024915,3.3734375));
#1142=CARTESIAN_POINT('',(32.6835427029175,-80.8407130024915,3.175));
#1143=CARTESIAN_POINT('',(32.6835427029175,-80.8407130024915,3.07578125));
#1144=CARTESIAN_POINT('',(32.6835427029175,-80.8407130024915,2.87734375));
#1145=CARTESIAN_POINT('',(32.6835427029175,-80.8407130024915,2.778125));
#1146=CARTESIAN_POINT('',(32.6835427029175,-80.8407130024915,2.5796875));
#1147=CARTESIAN_POINT('',(32.6835427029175,-80.8407130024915,2.48046875));
#1148=CARTESIAN_POINT('',(32.6835427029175,-80.8407130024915,2.28203125));
#1149=CARTESIAN_POINT('',(32.6835427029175,-80.8407130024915,2.1828125));
#1150=CARTESIAN_POINT('',(32.6835427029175,-80.8407130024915,1.984375));
#1151=CARTESIAN_POINT('',(32.6835427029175,-80.8407130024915,1.88515625));
#1152=CARTESIAN_POINT('',(32.6835427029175,-80.8407130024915,1.68671875));
#1153=CARTESIAN_POINT('',(32.6835427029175,-80.8407130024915,1.5875));
#1154=CARTESIAN_POINT('',(32.6835427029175,-80.8407130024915,1.3890625));
#1155=CARTESIAN_POINT('',(32.6835427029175,-80.8407130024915,1.28984375));
#1156=CARTESIAN_POINT('',(32.6835427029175,-80.8407130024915,1.09140625));
#1157=CARTESIAN_POINT('',(32.6835427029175,-80.8407130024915,0.992187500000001));
#1158=CARTESIAN_POINT('',(32.6835427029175,-80.8407130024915,0.793750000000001));
#1159=CARTESIAN_POINT('',(32.6835427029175,-80.8407130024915,0.69453125));
#1160=CARTESIAN_POINT('',(32.6835427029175,-80.8407130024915,0.49609375));
#1161=CARTESIAN_POINT('',(32.6835427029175,-80.8407130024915,0.396875));
#1162=CARTESIAN_POINT('',(32.6835427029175,-80.8407130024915,0.1984375));
#1163=CARTESIAN_POINT('',(32.6835427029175,-80.8407130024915,0.0992187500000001));
#1164=CARTESIAN_POINT('',(32.6835427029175,-80.8407130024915,0.));
#1165=B_SPLINE_CURVE_WITH_KNOTS('',3,(#1099,#1100,#1101,#1102,#1103,#1104,#1105,#1106,#1107,
#1108,#1109,#1110,#1111,#1112,#1113,#1114,#1115,#1116,#1117,#1118,#1119,#1120,#1121,#1122,#1123,
#1124,#1125,#1126,#1127,#1128,#1129,#1130,#1131,#1132,#1133,#1134,#1135,#1136,#1137,#1138,#1139,
#1140,#1141,#1142,#1143,#1144,#1145,#1146,#1147,#1148,#1149,#1150,#1151,#1152,#1153,#1154,#1155,
#1156,#1157,#1158,#1159,#1160,#1161,#1162,#1163,#1164),.UNSPECIFIED.,.F.,.F.,(4,2,2,2,2,2,2,2,2,
2,2,2,2,2,2,2,2,2,2,2,2,2,2,2,2,2,2,2,2,2,2,2,4),(0.,0.29765625,0.5953125,0.892968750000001,
1.190625,1.48828125,1.7859375,2.08359375,2.38125,2.67890625,2.9765625,3.27421875,3.571875,
3.86953125,4.1671875,4.46484375,4.7625,5.06015625,5.3578125,5.65546875,5.953125,6.25078125,
6.5484375,6.84609375,7.14375,7.44140625,7.7390625,8.03671875,8.334375,8.63203125,8.9296875,
9.22734375,9.525),.UNSPECIFIED.);
#1166=EDGE_CURVE('BSEAM405',#198,#383,#1165,.T.);
#1167=ORIENTED_EDGE('',*,*,#199,.T.);
#1168=ORIENTED_EDGE('',*,*,#384,.F.);
#1169=ORIENTED_EDGE('',*,*,#1166,.T.);
#1170=ORIENTED_EDGE('',*,*,#1166,.F.);
#1171=EDGE_LOOP('',(#1167,#1169,#1168,#1170));
#1172=FACE_BOUND('',#1171,.T.);
#1173=ADVANCED_FACE('F405',(#1172),#1098,.F.);
#1174=CARTESIAN_POINT('',(34.1835427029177,-109.159286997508,9.525));
#1175=DIRECTION('',(0.,0.,-1.));
#1176=DIRECTION('',(-1.,0.,0.));
#1177=AXIS2_PLACEMENT_3D('',#1174,#1175,#1176);
#1178=CYLINDRICAL_SURFACE('',#1177,1.49999999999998);
#1179=CARTESIAN_POINT('',(32.6835427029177,-109.159286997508,9.525));
#1180=CARTESIAN_POINT('',(32.6835427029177,-109.159286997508,9.42578125));
#1181=CARTESIAN_POINT('',(32.6835427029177,-109.159286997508,9.3265625));
#1182=CARTESIAN_POINT('',(32.6835427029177,-109.159286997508,9.128125));
#1183=CARTESIAN_POINT('',(32.6835427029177,-109.159286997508,9.02890625));
#1184=CARTESIAN_POINT('',(32.6835427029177,-109.159286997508,8.83046875));
#1185=CARTESIAN_POINT('',(32.6835427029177,-109.159286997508,8.73125));
#1186=CARTESIAN_POINT('',(32.6835427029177,-109.159286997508,8.5328125));
#1187=CARTESIAN_POINT('',(32.6835427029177,-109.159286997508,8.43359375));
#1188=CARTESIAN_POINT('',(32.6835427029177,-109.159286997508,8.23515625));
#1189=CARTESIAN_POINT('',(32.6835427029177,-109.159286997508,8.1359375));
#1190=CARTESIAN_POINT('',(32.6835427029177,-109.159286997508,7.9375));
#1191=CARTESIAN_POINT('',(32.6835427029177,-109.159286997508,7.83828125));
#1192=CARTESIAN_POINT('',(32.6835427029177,-109.159286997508,7.63984375));
#1193=CARTESIAN_POINT('',(32.6835427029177,-109.159286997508,7.540625));
#1194=CARTESIAN_POINT('',(32.6835427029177,-109.159286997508,7.3421875));
#1195=CARTESIAN_POINT('',(32.6835427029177,-109.159286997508,7.24296875));
#1196=CARTESIAN_POINT('',(32.6835427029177,-109.159286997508,7.04453125));
#1197=CARTESIAN_POINT('',(32.6835427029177,-109.159286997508,6.9453125));
#1198=CARTESIAN_POINT('',(32.6835427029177,-109.159286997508,6.746875));
#1199=CARTESIAN_POINT('',(32.6835427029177,-109.159286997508,6.64765625));
#1200=CARTESIAN_POINT('',(32.6835427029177,-109.159286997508,6.44921875));
#1201=CARTESIAN_POINT('',(32.6835427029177,-109.159286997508,6.35));
#1202=CARTESIAN_POINT('',(32.6835427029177,-109.159286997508,6.1515625));
#1203=CARTESIAN_POINT('',(32.6835427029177,-109.159286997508,6.05234375));
#1204=CARTESIAN_POINT('',(32.6835427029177,-109.159286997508,5.85390625));
#1205=CARTESIAN_POINT('',(32.6835427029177,-109.159286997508,5.7546875));
#1206=CARTESIAN_POINT('',(32.6835427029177,-109.159286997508,5.55625));
#1207=CARTESIAN_POINT('',(32.6835427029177,-109.159286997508,5.45703125));
#1208=CARTESIAN_POINT('',(32.6835427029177,-109.159286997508,5.25859375));
#1209=CARTESIAN_POINT('',(32.6835427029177,-109.159286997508,5.159375));
#1210=CARTESIAN_POINT('',(32.6835427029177,-109.159286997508,4.9609375));
#1211=CARTESIAN_POINT('',(32.6835427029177,-109.159286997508,4.86171875));
#1212=CARTESIAN_POINT('',(32.6835427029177,-109.159286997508,4.66328125));
#1213=CARTESIAN_POINT('',(32.6835427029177,-109.159286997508,4.5640625));
#1214=CARTESIAN_POINT('',(32.6835427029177,-109.159286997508,4.365625));
#1215=CARTESIAN_POINT('',(32.6835427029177,-109.159286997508,4.26640625));
#1216=CARTESIAN_POINT('',(32.6835427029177,-109.159286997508,4.06796875));
#1217=CARTESIAN_POINT('',(32.6835427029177,-109.159286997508,3.96875));
#1218=CARTESIAN_POINT('',(32.6835427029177,-109.159286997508,3.7703125));
#1219=CARTESIAN_POINT('',(32.6835427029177,-109.159286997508,3.67109375));
#1220=CARTESIAN_POINT('',(32.6835427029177,-109.159286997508,3.47265625));
#1221=CARTESIAN_POINT('',(32.6835427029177,-109.159286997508,3.3734375));
#1222=CARTESIAN_POINT('',(32.6835427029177,-109.159286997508,3.175));
#1223=CARTESIAN_POINT('',(32.6835427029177,-109.159286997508,3.07578125));
#1224=CARTESIAN_POINT('',(32.6835427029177,-109.159286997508,2.87734375));
#1225=CARTESIAN_POINT('',(32.6835427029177,-109.159286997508,2.778125));
#1226=CARTESIAN_POINT('',(32.6835427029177,-109.159286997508,2.5796875));
#1227=CARTESIAN_POINT('',(32.6835427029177,-109.159286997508,2.48046875));
#1228=CARTESIAN_POINT('',(32.6835427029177,-109.159286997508,2.28203125));
#1229=CARTESIAN_POINT('',(32.6835427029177,-109.159286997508,2.1828125));
#1230=CARTESIAN_POINT('',(32.6835427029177,-109.159286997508,1.984375));
#1231=CARTESIAN_POINT('',(32.6835427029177,-109.159286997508,1.88515625));
#1232=CARTESIAN_POINT('',(32.6835427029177,-109.159286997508,1.68671875));
#1233=CARTESIAN_POINT('',(32.6835427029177,-109.159286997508,1.5875));
#1234=CARTESIAN_POINT('',(32.6835427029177,-109.159286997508,1.3890625));
#1235=CARTESIAN_POINT('',(32.6835427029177,-109.159286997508,1.28984375));
#1236=CARTESIAN_POINT('',(32.6835427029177,-109.159286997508,1.09140625));
#1237=CARTESIAN_POINT('',(32.6835427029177,-109.159286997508,0.992187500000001));
#1238=CARTESIAN_POINT('',(32.6835427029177,-109.159286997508,0.793750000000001));
#1239=CARTESIAN_POINT('',(32.6835427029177,-109.159286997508,0.69453125));
#1240=CARTESIAN_POINT('',(32.6835427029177,-109.159286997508,0.49609375));
#1241=CARTESIAN_POINT('',(32.6835427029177,-109.159286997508,0.396875));
#1242=CARTESIAN_POINT('',(32.6835427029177,-109.159286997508,0.1984375));
#1243=CARTESIAN_POINT('',(32.6835427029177,-109.159286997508,0.0992187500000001));
#1244=CARTESIAN_POINT('',(32.6835427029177,-109.159286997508,0.));
#1245=B_SPLINE_CURVE_WITH_KNOTS('',3,(#1179,#1180,#1181,#1182,#1183,#1184,#1185,#1186,#1187,
#1188,#1189,#1190,#1191,#1192,#1193,#1194,#1195,#1196,#1197,#1198,#1199,#1200,#1201,#1202,#1203,
#1204,#1205,#1206,#1207,#1208,#1209,#1210,#1211,#1212,#1213,#1214,#1215,#1216,#1217,#1218,#1219,
#1220,#1221,#1222,#1223,#1224,#1225,#1226,#1227,#1228,#1229,#1230,#1231,#1232,#1233,#1234,#1235,
#1236,#1237,#1238,#1239,#1240,#1241,#1242,#1243,#1244),.UNSPECIFIED.,.F.,.F.,(4,2,2,2,2,2,2,2,2,
2,2,2,2,2,2,2,2,2,2,2,2,2,2,2,2,2,2,2,2,2,2,2,4),(0.,0.29765625,0.5953125,0.892968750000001,
1.190625,1.48828125,1.7859375,2.08359375,2.38125,2.67890625,2.9765625,3.27421875,3.571875,
3.86953125,4.1671875,4.46484375,4.7625,5.06015625,5.3578125,5.65546875,5.953125,6.25078125,
6.5484375,6.84609375,7.14375,7.44140625,7.7390625,8.03671875,8.334375,8.63203125,8.9296875,
9.22734375,9.525),.UNSPECIFIED.);
#1246=EDGE_CURVE('BSEAM415',#74,#394,#1245,.T.);
#1247=ORIENTED_EDGE('',*,*,#75,.T.);
#1248=ORIENTED_EDGE('',*,*,#395,.F.);
#1249=ORIENTED_EDGE('',*,*,#1246,.T.);
#1250=ORIENTED_EDGE('',*,*,#1246,.F.);
#1251=EDGE_LOOP('',(#1247,#1249,#1248,#1250));
#1252=FACE_BOUND('',#1251,.T.);
#1253=ADVANCED_FACE('F415',(#1252),#1178,.F.);
#1254=CARTESIAN_POINT('',(14.1592869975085,-129.183542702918,9.525));
#1255=DIRECTION('',(0.,0.,-1.));
#1256=DIRECTION('',(-1.,0.,0.));
#1257=AXIS2_PLACEMENT_3D('',#1254,#1255,#1256);
#1258=CYLINDRICAL_SURFACE('',#1257,1.49999999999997);
#1259=CARTESIAN_POINT('',(12.6592869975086,-129.183542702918,9.525));
#1260=CARTESIAN_POINT('',(12.6592869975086,-129.183542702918,9.42578125));
#1261=CARTESIAN_POINT('',(12.6592869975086,-129.183542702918,9.3265625));
#1262=CARTESIAN_POINT('',(12.6592869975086,-129.183542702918,9.128125));
#1263=CARTESIAN_POINT('',(12.6592869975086,-129.183542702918,9.02890625));
#1264=CARTESIAN_POINT('',(12.6592869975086,-129.183542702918,8.83046875));
#1265=CARTESIAN_POINT('',(12.6592869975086,-129.183542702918,8.73125));
#1266=CARTESIAN_POINT('',(12.6592869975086,-129.183542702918,8.5328125));
#1267=CARTESIAN_POINT('',(12.6592869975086,-129.183542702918,8.43359375));
#1268=CARTESIAN_POINT('',(12.6592869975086,-129.183542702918,8.23515625));
#1269=CARTESIAN_POINT('',(12.6592869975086,-129.183542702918,8.1359375));
#1270=CARTESIAN_POINT('',(12.6592869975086,-129.183542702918,7.9375));
#1271=CARTESIAN_POINT('',(12.6592869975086,-129.183542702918,7.83828125));
#1272=CARTESIAN_POINT('',(12.6592869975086,-129.183542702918,7.63984375));
#1273=CARTESIAN_POINT('',(12.6592869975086,-129.183542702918,7.540625));
#1274=CARTESIAN_POINT('',(12.6592869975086,-129.183542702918,7.3421875));
#1275=CARTESIAN_POINT('',(12.6592869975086,-129.183542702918,7.24296875));
#1276=CARTESIAN_POINT('',(12.6592869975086,-129.183542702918,7.04453125));
#1277=CARTESIAN_POINT('',(12.6592869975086,-129.183542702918,6.9453125));
#1278=CARTESIAN_POINT('',(12.6592869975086,-129.183542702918,6.746875));
#1279=CARTESIAN_POINT('',(12.6592869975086,-129.183542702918,6.64765625));
#1280=CARTESIAN_POINT('',(12.6592869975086,-129.183542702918,6.44921875));
#1281=CARTESIAN_POINT('',(12.6592869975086,-129.183542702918,6.35));
#1282=CARTESIAN_POINT('',(12.6592869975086,-129.183542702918,6.1515625));
#1283=CARTESIAN_POINT('',(12.6592869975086,-129.183542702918,6.05234375));
#1284=CARTESIAN_POINT('',(12.6592869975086,-129.183542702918,5.85390625));
#1285=CARTESIAN_POINT('',(12.6592869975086,-129.183542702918,5.7546875));
#1286=CARTESIAN_POINT('',(12.6592869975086,-129.183542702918,5.55625));
#1287=CARTESIAN_POINT('',(12.6592869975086,-129.183542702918,5.45703125));
#1288=CARTESIAN_POINT('',(12.6592869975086,-129.183542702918,5.25859375));
#1289=CARTESIAN_POINT('',(12.6592869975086,-129.183542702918,5.159375));
#1290=CARTESIAN_POINT('',(12.6592869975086,-129.183542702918,4.9609375));
#1291=CARTESIAN_POINT('',(12.6592869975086,-129.183542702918,4.86171875));
#1292=CARTESIAN_POINT('',(12.6592869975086,-129.183542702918,4.66328125));
#1293=CARTESIAN_POINT('',(12.6592869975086,-129.183542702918,4.5640625));
#1294=CARTESIAN_POINT('',(12.6592869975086,-129.183542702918,4.365625));
#1295=CARTESIAN_POINT('',(12.6592869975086,-129.183542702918,4.26640625));
#1296=CARTESIAN_POINT('',(12.6592869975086,-129.183542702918,4.06796875));
#1297=CARTESIAN_POINT('',(12.6592869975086,-129.183542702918,3.96875));
#1298=CARTESIAN_POINT('',(12.6592869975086,-129.183542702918,3.7703125));
#1299=CARTESIAN_POINT('',(12.6592869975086,-129.183542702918,3.67109375));
#1300=CARTESIAN_POINT('',(12.6592869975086,-129.183542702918,3.47265625));
#1301=CARTESIAN_POINT('',(12.6592869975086,-129.183542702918,3.3734375));
#1302=CARTESIAN_POINT('',(12.6592869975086,-129.183542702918,3.175));
#1303=CARTESIAN_POINT('',(12.6592869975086,-129.183542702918,3.07578125));
#1304=CARTESIAN_POINT('',(12.6592869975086,-129.183542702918,2.87734375));
#1305=CARTESIAN_POINT('',(12.6592869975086,-129.183542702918,2.778125));
#1306=CARTESIAN_POINT('',(12.6592869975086,-129.183542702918,2.5796875));
#1307=CARTESIAN_POINT('',(12.6592869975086,-129.183542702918,2.48046875));
#1308=CARTESIAN_POINT('',(12.6592869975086,-129.183542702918,2.28203125));
#1309=CARTESIAN_POINT('',(12.6592869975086,-129.183542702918,2.1828125));
#1310=CARTESIAN_POINT('',(12.6592869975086,-129.183542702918,1.984375));
#1311=CARTESIAN_POINT('',(12.6592869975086,-129.183542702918,1.88515625));
#1312=CARTESIAN_POINT('',(12.6592869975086,-129.183542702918,1.68671875));
#1313=CARTESIAN_POINT('',(12.6592869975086,-129.183542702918,1.5875));
#1314=CARTESIAN_POINT('',(12.6592869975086,-129.183542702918,1.3890625));
#1315=CARTESIAN_POINT('',(12.6592869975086,-129.183542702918,1.28984375));
#1316=CARTESIAN_POINT('',(12.6592869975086,-129.183542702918,1.09140625));
#1317=CARTESIAN_POINT('',(12.6592869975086,-129.183542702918,0.992187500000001));
#1318=CARTESIAN_POINT('',(12.6592869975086,-129.183542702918,0.793750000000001));
#1319=CARTESIAN_POINT('',(12.6592869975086,-129.183542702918,0.69453125));
#1320=CARTESIAN_POINT('',(12.6592869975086,-129.183542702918,0.49609375));
#1321=CARTESIAN_POINT('',(12.6592869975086,-129.183542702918,0.396875));
#1322=CARTESIAN_POINT('',(12.6592869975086,-129.183542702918,0.1984375));
#1323=CARTESIAN_POINT('',(12.6592869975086,-129.183542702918,0.0992187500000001));
#1324=CARTESIAN_POINT('',(12.6592869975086,-129.183542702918,0.));
#1325=B_SPLINE_CURVE_WITH_KNOTS('',3,(#1259,#1260,#1261,#1262,#1263,#1264,#1265,#1266,#1267,
#1268,#1269,#1270,#1271,#1272,#1273,#1274,#1275,#1276,#1277,#1278,#1279,#1280,#1281,#1282,#1283,
#1284,#1285,#1286,#1287,#1288,#1289,#1290,#1291,#1292,#1293,#1294,#1295,#1296,#1297,#1298,#1299,
#1300,#1301,#1302,#1303,#1304,#1305,#1306,#1307,#1308,#1309,#1310,#1311,#1312,#1313,#1314,#1315,
#1316,#1317,#1318,#1319,#1320,#1321,#1322,#1323,#1324),.UNSPECIFIED.,.F.,.F.,(4,2,2,2,2,2,2,2,2,
2,2,2,2,2,2,2,2,2,2,2,2,2,2,2,2,2,2,2,2,2,2,2,4),(0.,0.29765625,0.5953125,0.892968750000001,
1.190625,1.48828125,1.7859375,2.08359375,2.38125,2.67890625,2.9765625,3.27421875,3.571875,
3.86953125,4.1671875,4.46484375,4.7625,5.06015625,5.3578125,5.65546875,5.953125,6.25078125,
6.5484375,6.84609375,7.14375,7.44140625,7.7390625,8.03671875,8.334375,8.63203125,8.9296875,
9.22734375,9.525),.UNSPECIFIED.);
#1326=EDGE_CURVE('BSEAM425',#209,#405,#1325,.T.);
#1327=ORIENTED_EDGE('',*,*,#210,.T.);
#1328=ORIENTED_EDGE('',*,*,#406,.F.);
#1329=ORIENTED_EDGE('',*,*,#1326,.T.);
#1330=ORIENTED_EDGE('',*,*,#1326,.F.);
#1331=EDGE_LOOP('',(#1327,#1329,#1328,#1330));
#1332=FACE_BOUND('',#1331,.T.);
#1333=ADVANCED_FACE('F425',(#1332),#1258,.F.);
#1334=CARTESIAN_POINT('',(-7.12499999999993,12.3408620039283,9.525));
#1335=DIRECTION('',(0.,0.,-1.));
#1336=DIRECTION('',(-1.,0.,0.));
#1337=AXIS2_PLACEMENT_3D('',#1334,#1335,#1336);
#1338=CYLINDRICAL_SURFACE('',#1337,3.);
#1339=CARTESIAN_POINT('',(-7.12499999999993,12.3408620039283,5.525));
#1340=DIRECTION('',(0.,0.,1.));
#1341=DIRECTION('',(1.,0.,0.));
#1342=AXIS2_PLACEMENT_3D('',#1339,#1340,#1341);
#1343=CIRCLE('',#1342,3.);
#1344=CARTESIAN_POINT('',(-10.1249999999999,12.3408620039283,5.525));
#1345=VERTEX_POINT('',#1344);
#1346=EDGE_CURVE('E11',#1345,#1345,#1343,.T.);
#1347=CARTESIAN_POINT('',(-10.1249999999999,12.3408620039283,5.525));
#1348=CARTESIAN_POINT('',(-10.1249999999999,12.3408620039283,5.56666666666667));
#1349=CARTESIAN_POINT('',(-10.1249999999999,12.3408620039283,5.60833333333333));
#1350=CARTESIAN_POINT('',(-10.1249999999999,12.3408620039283,5.69166666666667));
#1351=CARTESIAN_POINT('',(-10.1249999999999,12.3408620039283,5.73333333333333));
#1352=CARTESIAN_POINT('',(-10.1249999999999,12.3408620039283,5.81666666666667));
#1353=CARTESIAN_POINT('',(-10.1249999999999,12.3408620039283,5.85833333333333));
#1354=CARTESIAN_POINT('',(-10.1249999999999,12.3408620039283,5.94166666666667));
#1355=CARTESIAN_POINT('',(-10.1249999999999,12.3408620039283,5.98333333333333));
#1356=CARTESIAN_POINT('',(-10.1249999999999,12.3408620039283,6.06666666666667));
#1357=CARTESIAN_POINT('',(-10.1249999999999,12.3408620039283,6.10833333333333));
#1358=CARTESIAN_POINT('',(-10.1249999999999,12.3408620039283,6.19166666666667));
#1359=CARTESIAN_POINT('',(-10.1249999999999,12.3408620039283,6.23333333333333));
#1360=CARTESIAN_POINT('',(-10.1249999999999,12.3408620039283,6.31666666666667));
#1361=CARTESIAN_POINT('',(-10.1249999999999,12.3408620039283,6.35833333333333));
#1362=CARTESIAN_POINT('',(-10.1249999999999,12.3408620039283,6.44166666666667));
#1363=CARTESIAN_POINT('',(-10.1249999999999,12.3408620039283,6.48333333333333));
#1364=CARTESIAN_POINT('',(-10.1249999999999,12.3408620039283,6.56666666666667));
#1365=CARTESIAN_POINT('',(-10.1249999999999,12.3408620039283,6.60833333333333));
#1366=CARTESIAN_POINT('',(-10.1249999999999,12.3408620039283,6.69166666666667));
#1367=CARTESIAN_POINT('',(-10.1249999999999,12.3408620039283,6.73333333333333));
#1368=CARTESIAN_POINT('',(-10.1249999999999,12.3408620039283,6.81666666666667));
#1369=CARTESIAN_POINT('',(-10.1249999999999,12.3408620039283,6.85833333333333));
#1370=CARTESIAN_POINT('',(-10.1249999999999,12.3408620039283,6.94166666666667));
#1371=CARTESIAN_POINT('',(-10.1249999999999,12.3408620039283,6.98333333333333));
#1372=CARTESIAN_POINT('',(-10.1249999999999,12.3408620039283,7.06666666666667));
#1373=CARTESIAN_POINT('',(-10.1249999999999,12.3408620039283,7.10833333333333));
#1374=CARTESIAN_POINT('',(-10.1249999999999,12.3408620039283,7.19166666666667));
#1375=CARTESIAN_POINT('',(-10.1249999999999,12.3408620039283,7.23333333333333));
#1376=CARTESIAN_POINT('',(-10.1249999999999,12.3408620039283,7.31666666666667));
#1377=CARTESIAN_POINT('',(-10.1249999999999,12.3408620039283,7.35833333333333));
#1378=CARTESIAN_POINT('',(-10.1249999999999,12.3408620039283,7.44166666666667));
#1379=CARTESIAN_POINT('',(-10.1249999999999,12.3408620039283,7.48333333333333));
#1380=CARTESIAN_POINT('',(-10.1249999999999,12.3408620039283,7.56666666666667));
#1381=CARTESIAN_POINT('',(-10.1249999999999,12.3408620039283,7.60833333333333));
#1382=CARTESIAN_POINT('',(-10.1249999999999,12.3408620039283,7.69166666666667));
#1383=CARTESIAN_POINT('',(-10.1249999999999,12.3408620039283,7.73333333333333));
#1384=CARTESIAN_POINT('',(-10.1249999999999,12.3408620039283,7.81666666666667));
#1385=CARTESIAN_POINT('',(-10.1249999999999,12.3408620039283,7.85833333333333));
#1386=CARTESIAN_POINT('',(-10.1249999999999,12.3408620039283,7.94166666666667));
#1387=CARTESIAN_POINT('',(-10.1249999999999,12.3408620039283,7.98333333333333));
#1388=CARTESIAN_POINT('',(-10.1249999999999,12.3408620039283,8.06666666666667));
#1389=CARTESIAN_POINT('',(-10.1249999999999,12.3408620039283,8.10833333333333));
#1390=CARTESIAN_POINT('',(-10.1249999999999,12.3408620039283,8.19166666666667));
#1391=CARTESIAN_POINT('',(-10.1249999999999,12.3408620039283,8.23333333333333));
#1392=CARTESIAN_POINT('',(-10.1249999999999,12.3408620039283,8.31666666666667));
#1393=CARTESIAN_POINT('',(-10.1249999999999,12.3408620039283,8.35833333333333));
#1394=CARTESIAN_POINT('',(-10.1249999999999,12.3408620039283,8.44166666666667));
#1395=CARTESIAN_POINT('',(-10.1249999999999,12.3408620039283,8.48333333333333));
#1396=CARTESIAN_POINT('',(-10.1249999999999,12.3408620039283,8.56666666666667));
#1397=CARTESIAN_POINT('',(-10.1249999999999,12.3408620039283,8.60833333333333));
#1398=CARTESIAN_POINT('',(-10.1249999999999,12.3408620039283,8.69166666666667));
#1399=CARTESIAN_POINT('',(-10.1249999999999,12.3408620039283,8.73333333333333));
#1400=CARTESIAN_POINT('',(-10.1249999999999,12.3408620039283,8.81666666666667));
#1401=CARTESIAN_POINT('',(-10.1249999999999,12.3408620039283,8.85833333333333));
#1402=CARTESIAN_POINT('',(-10.1249999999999,12.3408620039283,8.94166666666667));
#1403=CARTESIAN_POINT('',(-10.1249999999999,12.3408620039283,8.98333333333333));
#1404=CARTESIAN_POINT('',(-10.1249999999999,12.3408620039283,9.06666666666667));
#1405=CARTESIAN_POINT('',(-10.1249999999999,12.3408620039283,9.10833333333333));
#1406=CARTESIAN_POINT('',(-10.1249999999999,12.3408620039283,9.19166666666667));
#1407=CARTESIAN_POINT('',(-10.1249999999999,12.3408620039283,9.23333333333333));
#1408=CARTESIAN_POINT('',(-10.1249999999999,12.3408620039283,9.31666666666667));
#1409=CARTESIAN_POINT('',(-10.1249999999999,12.3408620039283,9.35833333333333));
#1410=CARTESIAN_POINT('',(-10.1249999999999,12.3408620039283,9.44166666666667));
#1411=CARTESIAN_POINT('',(-10.1249999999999,12.3408620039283,9.48333333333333));
#1412=CARTESIAN_POINT('',(-10.1249999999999,12.3408620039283,9.525));
#1413=B_SPLINE_CURVE_WITH_KNOTS('',3,(#1347,#1348,#1349,#1350,#1351,#1352,#1353,#1354,#1355,
#1356,#1357,#1358,#1359,#1360,#1361,#1362,#1363,#1364,#1365,#1366,#1367,#1368,#1369,#1370,#1371,
#1372,#1373,#1374,#1375,#1376,#1377,#1378,#1379,#1380,#1381,#1382,#1383,#1384,#1385,#1386,#1387,
#1388,#1389,#1390,#1391,#1392,#1393,#1394,#1395,#1396,#1397,#1398,#1399,#1400,#1401,#1402,#1403,
#1404,#1405,#1406,#1407,#1408,#1409,#1410,#1411,#1412),.UNSPECIFIED.,.F.,.F.,(4,2,2,2,2,2,2,2,2,
2,2,2,2,2,2,2,2,2,2,2,2,2,2,2,2,2,2,2,2,2,2,2,4),(0.,0.124999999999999,0.249999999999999,
0.374999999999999,0.5,0.625,0.75,0.875,1.,1.125,1.25,1.375,1.5,1.625,1.75,1.875,2.,2.125,2.25,
2.375,2.5,2.625,2.75,2.875,3.,3.125,3.25,3.375,3.5,3.625,3.75,3.875,4.),.UNSPECIFIED.);
#1414=EDGE_CURVE('BSEAM435',#1345,#63,#1413,.T.);
#1415=ORIENTED_EDGE('',*,*,#1346,.F.);
#1416=ORIENTED_EDGE('',*,*,#64,.T.);
#1417=ORIENTED_EDGE('',*,*,#1414,.T.);
#1418=ORIENTED_EDGE('',*,*,#1414,.F.);
#1419=EDGE_LOOP('',(#1415,#1417,#1416,#1418));
#1420=FACE_BOUND('',#1419,.T.);
#1421=ADVANCED_FACE('F435',(#1420),#1338,.F.);
#1422=CARTESIAN_POINT('',(12.9903810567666,7.49999999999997,9.525));
#1423=DIRECTION('',(0.,0.,-1.));
#1424=DIRECTION('',(-1.,0.,0.));
#1425=AXIS2_PLACEMENT_3D('',#1422,#1423,#1424);
#1426=CYLINDRICAL_SURFACE('',#1425,2.);
#1427=CARTESIAN_POINT('',(10.9903810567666,7.49999999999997,9.525));
#1428=CARTESIAN_POINT('',(10.9903810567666,7.49999999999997,9.42578125));
#1429=CARTESIAN_POINT('',(10.9903810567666,7.49999999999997,9.3265625));
#1430=CARTESIAN_POINT('',(10.9903810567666,7.49999999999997,9.128125));
#1431=CARTESIAN_POINT('',(10.9903810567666,7.49999999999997,9.02890625));
#1432=CARTESIAN_POINT('',(10.9903810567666,7.49999999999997,8.83046875));
#1433=CARTESIAN_POINT('',(10.9903810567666,7.49999999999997,8.73125));
#1434=CARTESIAN_POINT('',(10.9903810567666,7.49999999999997,8.5328125));
#1435=CARTESIAN_POINT('',(10.9903810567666,7.49999999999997,8.43359375));
#1436=CARTESIAN_POINT('',(10.9903810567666,7.49999999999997,8.23515625));
#1437=CARTESIAN_POINT('',(10.9903810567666,7.49999999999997,8.1359375));
#1438=CARTESIAN_POINT('',(10.9903810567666,7.49999999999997,7.9375));
#1439=CARTESIAN_POINT('',(10.9903810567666,7.49999999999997,7.83828125));
#1440=CARTESIAN_POINT('',(10.9903810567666,7.49999999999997,7.63984375));
#1441=CARTESIAN_POINT('',(10.9903810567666,7.49999999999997,7.540625));
#1442=CARTESIAN_POINT('',(10.9903810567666,7.49999999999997,7.3421875));
#1443=CARTESIAN_POINT('',(10.9903810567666,7.49999999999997,7.24296875));
#1444=CARTESIAN_POINT('',(10.9903810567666,7.49999999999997,7.04453125));
#1445=CARTESIAN_POINT('',(10.9903810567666,7.49999999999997,6.9453125));
#1446=CARTESIAN_POINT('',(10.9903810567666,7.49999999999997,6.746875));
#1447=CARTESIAN_POINT('',(10.9903810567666,7.49999999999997,6.64765625));
#1448=CARTESIAN_POINT('',(10.9903810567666,7.49999999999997,6.44921875));
#1449=CARTESIAN_POINT('',(10.9903810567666,7.49999999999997,6.35));
#1450=CARTESIAN_POINT('',(10.9903810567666,7.49999999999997,6.1515625));
#1451=CARTESIAN_POINT('',(10.9903810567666,7.49999999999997,6.05234375));
#1452=CARTESIAN_POINT('',(10.9903810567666,7.49999999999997,5.85390625));
#1453=CARTESIAN_POINT('',(10.9903810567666,7.49999999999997,5.7546875));
#1454=CARTESIAN_POINT('',(10.9903810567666,7.49999999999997,5.55625));
#1455=CARTESIAN_POINT('',(10.9903810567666,7.49999999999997,5.45703125));
#1456=CARTESIAN_POINT('',(10.9903810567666,7.49999999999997,5.25859375));
#1457=CARTESIAN_POINT('',(10.9903810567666,7.49999999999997,5.159375));
#1458=CARTESIAN_POINT('',(10.9903810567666,7.49999999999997,4.9609375));
#1459=CARTESIAN_POINT('',(10.9903810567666,7.49999999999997,4.86171875));
#1460=CARTESIAN_POINT('',(10.9903810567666,7.49999999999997,4.66328125));
#1461=CARTESIAN_POINT('',(10.9903810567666,7.49999999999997,4.5640625));
#1462=CARTESIAN_POINT('',(10.9903810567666,7.49999999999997,4.365625));
#1463=CARTESIAN_POINT('',(10.9903810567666,7.49999999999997,4.26640625));
#1464=CARTESIAN_POINT('',(10.9903810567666,7.49999999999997,4.06796875));
#1465=CARTESIAN_POINT('',(10.9903810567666,7.49999999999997,3.96875));
#1466=CARTESIAN_POINT('',(10.9903810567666,7.49999999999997,3.7703125));
#1467=CARTESIAN_POINT('',(10.9903810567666,7.49999999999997,3.67109375));
#1468=CARTESIAN_POINT('',(10.9903810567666,7.49999999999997,3.47265625));
#1469=CARTESIAN_POINT('',(10.9903810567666,7.49999999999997,3.3734375));
#1470=CARTESIAN_POINT('',(10.9903810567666,7.49999999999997,3.175));
#1471=CARTESIAN_POINT('',(10.9903810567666,7.49999999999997,3.07578125));
#1472=CARTESIAN_POINT('',(10.9903810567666,7.49999999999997,2.87734375));
#1473=CARTESIAN_POINT('',(10.9903810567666,7.49999999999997,2.778125));
#1474=CARTESIAN_POINT('',(10.9903810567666,7.49999999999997,2.5796875));
#1475=CARTESIAN_POINT('',(10.9903810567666,7.49999999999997,2.48046875));
#1476=CARTESIAN_POINT('',(10.9903810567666,7.49999999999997,2.28203125));
#1477=CARTESIAN_POINT('',(10.9903810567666,7.49999999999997,2.1828125));
#1478=CARTESIAN_POINT('',(10.9903810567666,7.49999999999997,1.984375));
#1479=CARTESIAN_POINT('',(10.9903810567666,7.49999999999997,1.88515625));
#1480=CARTESIAN_POINT('',(10.9903810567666,7.49999999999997,1.68671875));
#1481=CARTESIAN_POINT('',(10.9903810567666,7.49999999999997,1.5875));
#1482=CARTESIAN_POINT('',(10.9903810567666,7.49999999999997,1.3890625));
#1483=CARTESIAN_POINT('',(10.9903810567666,7.49999999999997,1.28984375));
#1484=CARTESIAN_POINT('',(10.9903810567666,7.49999999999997,1.09140625));
#1485=CARTESIAN_POINT('',(10.9903810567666,7.49999999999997,0.992187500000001));
#1486=CARTESIAN_POINT('',(10.9903810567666,7.49999999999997,0.793750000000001));
#1487=CARTESIAN_POINT('',(10.9903810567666,7.49999999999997,0.69453125));
#1488=CARTESIAN_POINT('',(10.9903810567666,7.49999999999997,0.49609375));
#1489=CARTESIAN_POINT('',(10.9903810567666,7.49999999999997,0.396875));
#1490=CARTESIAN_POINT('',(10.9903810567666,7.49999999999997,0.1984375));
#1491=CARTESIAN_POINT('',(10.9903810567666,7.49999999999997,0.0992187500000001));
#1492=CARTESIAN_POINT('',(10.9903810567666,7.49999999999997,0.));
#1493=B_SPLINE_CURVE_WITH_KNOTS('',3,(#1427,#1428,#1429,#1430,#1431,#1432,#1433,#1434,#1435,
#1436,#1437,#1438,#1439,#1440,#1441,#1442,#1443,#1444,#1445,#1446,#1447,#1448,#1449,#1450,#1451,
#1452,#1453,#1454,#1455,#1456,#1457,#1458,#1459,#1460,#1461,#1462,#1463,#1464,#1465,#1466,#1467,
#1468,#1469,#1470,#1471,#1472,#1473,#1474,#1475,#1476,#1477,#1478,#1479,#1480,#1481,#1482,#1483,
#1484,#1485,#1486,#1487,#1488,#1489,#1490,#1491,#1492),.UNSPECIFIED.,.F.,.F.,(4,2,2,2,2,2,2,2,2,
2,2,2,2,2,2,2,2,2,2,2,2,2,2,2,2,2,2,2,2,2,2,2,4),(0.,0.297656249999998,0.595312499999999,
0.892968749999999,1.190625,1.48828125,1.7859375,2.08359375,2.38125,2.67890625,2.9765625,
3.27421875,3.571875,3.86953125,4.1671875,4.46484375,4.7625,5.06015625,5.3578125,5.65546875,
5.953125,6.25078125,6.5484375,6.84609375,7.14375,7.44140625,7.7390625,8.03671875,8.334375,
8.63203125,8.9296875,9.22734375,9.525),.UNSPECIFIED.);
#1494=EDGE_CURVE('BSEAM444',#220,#416,#1493,.T.);
#1495=ORIENTED_EDGE('',*,*,#221,.T.);
#1496=ORIENTED_EDGE('',*,*,#417,.F.);
#1497=ORIENTED_EDGE('',*,*,#1494,.T.);
#1498=ORIENTED_EDGE('',*,*,#1494,.F.);
#1499=EDGE_LOOP('',(#1495,#1497,#1496,#1498));
#1500=FACE_BOUND('',#1499,.T.);
#1501=ADVANCED_FACE('F444',(#1500),#1426,.F.);
#1502=CARTESIAN_POINT('',(12.9903810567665,-7.50000000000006,9.525));
#1503=DIRECTION('',(0.,0.,-1.));
#1504=DIRECTION('',(-1.,0.,0.));
#1505=AXIS2_PLACEMENT_3D('',#1502,#1503,#1504);
#1506=CYLINDRICAL_SURFACE('',#1505,2.);
#1507=CARTESIAN_POINT('',(10.9903810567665,-7.50000000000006,9.525));
#1508=CARTESIAN_POINT('',(10.9903810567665,-7.50000000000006,9.42578125));
#1509=CARTESIAN_POINT('',(10.9903810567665,-7.50000000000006,9.3265625));
#1510=CARTESIAN_POINT('',(10.9903810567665,-7.50000000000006,9.128125));
#1511=CARTESIAN_POINT('',(10.9903810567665,-7.50000000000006,9.02890625));
#1512=CARTESIAN_POINT('',(10.9903810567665,-7.50000000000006,8.83046875));
#1513=CARTESIAN_POINT('',(10.9903810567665,-7.50000000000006,8.73125));
#1514=CARTESIAN_POINT('',(10.9903810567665,-7.50000000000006,8.5328125));
#1515=CARTESIAN_POINT('',(10.9903810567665,-7.50000000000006,8.43359375));
#1516=CARTESIAN_POINT('',(10.9903810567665,-7.50000000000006,8.23515625));
#1517=CARTESIAN_POINT('',(10.9903810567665,-7.50000000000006,8.1359375));
#1518=CARTESIAN_POINT('',(10.9903810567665,-7.50000000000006,7.9375));
#1519=CARTESIAN_POINT('',(10.9903810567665,-7.50000000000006,7.83828125));
#1520=CARTESIAN_POINT('',(10.9903810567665,-7.50000000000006,7.63984375));
#1521=CARTESIAN_POINT('',(10.9903810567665,-7.50000000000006,7.540625));
#1522=CARTESIAN_POINT('',(10.9903810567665,-7.50000000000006,7.3421875));
#1523=CARTESIAN_POINT('',(10.9903810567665,-7.50000000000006,7.24296875));
#1524=CARTESIAN_POINT('',(10.9903810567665,-7.50000000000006,7.04453125));
#1525=CARTESIAN_POINT('',(10.9903810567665,-7.50000000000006,6.9453125));
#1526=CARTESIAN_POINT('',(10.9903810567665,-7.50000000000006,6.746875));
#1527=CARTESIAN_POINT('',(10.9903810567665,-7.50000000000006,6.64765625));
#1528=CARTESIAN_POINT('',(10.9903810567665,-7.50000000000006,6.44921875));
#1529=CARTESIAN_POINT('',(10.9903810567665,-7.50000000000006,6.35));
#1530=CARTESIAN_POINT('',(10.9903810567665,-7.50000000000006,6.1515625));
#1531=CARTESIAN_POINT('',(10.9903810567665,-7.50000000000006,6.05234375));
#1532=CARTESIAN_POINT('',(10.9903810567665,-7.50000000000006,5.85390625));
#1533=CARTESIAN_POINT('',(10.9903810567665,-7.50000000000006,5.7546875));
#1534=CARTESIAN_POINT('',(10.9903810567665,-7.50000000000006,5.55625));
#1535=CARTESIAN_POINT('',(10.9903810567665,-7.50000000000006,5.45703125));
#1536=CARTESIAN_POINT('',(10.9903810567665,-7.50000000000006,5.25859375));
#1537=CARTESIAN_POINT('',(10.9903810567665,-7.50000000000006,5.159375));
#1538=CARTESIAN_POINT('',(10.9903810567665,-7.50000000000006,4.9609375));
#1539=CARTESIAN_POINT('',(10.9903810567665,-7.50000000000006,4.86171875));
#1540=CARTESIAN_POINT('',(10.9903810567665,-7.50000000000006,4.66328125));
#1541=CARTESIAN_POINT('',(10.9903810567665,-7.50000000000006,4.5640625));
#1542=CARTESIAN_POINT('',(10.9903810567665,-7.50000000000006,4.365625));
#1543=CARTESIAN_POINT('',(10.9903810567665,-7.50000000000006,4.26640625));
#1544=CARTESIAN_POINT('',(10.9903810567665,-7.50000000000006,4.06796875));
#1545=CARTESIAN_POINT('',(10.9903810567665,-7.50000000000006,3.96875));
#1546=CARTESIAN_POINT('',(10.9903810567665,-7.50000000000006,3.7703125));
#1547=CARTESIAN_POINT('',(10.9903810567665,-7.50000000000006,3.67109375));
#1548=CARTESIAN_POINT('',(10.9903810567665,-7.50000000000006,3.47265625));
#1549=CARTESIAN_POINT('',(10.9903810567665,-7.50000000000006,3.3734375));
#1550=CARTESIAN_POINT('',(10.9903810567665,-7.50000000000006,3.175));
#1551=CARTESIAN_POINT('',(10.9903810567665,-7.50000000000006,3.07578125));
#1552=CARTESIAN_POINT('',(10.9903810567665,-7.50000000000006,2.87734375));
#1553=CARTESIAN_POINT('',(10.9903810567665,-7.50000000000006,2.778125));
#1554=CARTESIAN_POINT('',(10.9903810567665,-7.50000000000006,2.5796875));
#1555=CARTESIAN_POINT('',(10.9903810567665,-7.50000000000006,2.48046875));
#1556=CARTESIAN_POINT('',(10.9903810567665,-7.50000000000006,2.28203125));
#1557=CARTESIAN_POINT('',(10.9903810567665,-7.50000000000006,2.1828125));
#1558=CARTESIAN_POINT('',(10.9903810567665,-7.50000000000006,1.984375));
#1559=CARTESIAN_POINT('',(10.9903810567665,-7.50000000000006,1.88515625));
#1560=CARTESIAN_POINT('',(10.9903810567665,-7.50000000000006,1.68671875));
#1561=CARTESIAN_POINT('',(10.9903810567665,-7.50000000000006,1.5875));
#1562=CARTESIAN_POINT('',(10.9903810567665,-7.50000000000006,1.3890625));
#1563=CARTESIAN_POINT('',(10.9903810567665,-7.50000000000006,1.28984375));
#1564=CARTESIAN_POINT('',(10.9903810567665,-7.50000000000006,1.09140625));
#1565=CARTESIAN_POINT('',(10.9903810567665,-7.50000000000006,0.992187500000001));
#1566=CARTESIAN_POINT('',(10.9903810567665,-7.50000000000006,0.793750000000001));
#1567=CARTESIAN_POINT('',(10.9903810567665,-7.50000000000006,0.69453125));
#1568=CARTESIAN_POINT('',(10.9903810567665,-7.50000000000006,0.49609375));
#1569=CARTESIAN_POINT('',(10.9903810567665,-7.50000000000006,0.396875));
#1570=CARTESIAN_POINT('',(10.9903810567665,-7.50000000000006,0.1984375));
#1571=CARTESIAN_POINT('',(10.9903810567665,-7.50000000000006,0.0992187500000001));
#1572=CARTESIAN_POINT('',(10.9903810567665,-7.50000000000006,0.));
#1573=B_SPLINE_CURVE_WITH_KNOTS('',3,(#1507,#1508,#1509,#1510,#1511,#1512,#1513,#1514,#1515,
#1516,#1517,#1518,#1519,#1520,#1521,#1522,#1523,#1524,#1525,#1526,#1527,#1528,#1529,#1530,#1531,
#1532,#1533,#1534,#1535,#1536,#1537,#1538,#1539,#1540,#1541,#1542,#1543,#1544,#1545,#1546,#1547,
#1548,#1549,#1550,#1551,#1552,#1553,#1554,#1555,#1556,#1557,#1558,#1559,#1560,#1561,#1562,#1563,
#1564,#1565,#1566,#1567,#1568,#1569,#1570,#1571,#1572),.UNSPECIFIED.,.F.,.F.,(4,2,2,2,2,2,2,2,2,
2,2,2,2,2,2,2,2,2,2,2,2,2,2,2,2,2,2,2,2,2,2,2,4),(0.,0.297656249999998,0.595312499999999,
0.892968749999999,1.190625,1.48828125,1.7859375,2.08359375,2.38125,2.67890625,2.9765625,
3.27421875,3.571875,3.86953125,4.1671875,4.46484375,4.7625,5.06015625,5.3578125,5.65546875,
5.953125,6.25078125,6.5484375,6.84609375,7.14375,7.44140625,7.7390625,8.03671875,8.334375,
8.63203125,8.9296875,9.22734375,9.525),.UNSPECIFIED.);
#1574=EDGE_CURVE('BSEAM455',#52,#427,#1573,.T.);
#1575=ORIENTED_EDGE('',*,*,#53,.T.);
#1576=ORIENTED_EDGE('',*,*,#428,.F.);
#1577=ORIENTED_EDGE('',*,*,#1574,.T.);
#1578=ORIENTED_EDGE('',*,*,#1574,.F.);
#1579=EDGE_LOOP('',(#1575,#1577,#1576,#1578));
#1580=FACE_BOUND('',#1579,.T.);
#1581=ADVANCED_FACE('F455',(#1580),#1506,.F.);
#1582=CARTESIAN_POINT('',(-1.04744440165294E-13,-15.,9.525));
#1583=DIRECTION('',(0.,0.,-1.));
#1584=DIRECTION('',(-1.,0.,0.));
#1585=AXIS2_PLACEMENT_3D('',#1582,#1583,#1584);
#1586=CYLINDRICAL_SURFACE('',#1585,2.);
#1587=CARTESIAN_POINT('',(-2.0000000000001,-15.,9.525));
#1588=CARTESIAN_POINT('',(-2.0000000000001,-15.,9.42578125));
#1589=CARTESIAN_POINT('',(-2.0000000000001,-15.,9.3265625));
#1590=CARTESIAN_POINT('',(-2.0000000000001,-15.,9.128125));
#1591=CARTESIAN_POINT('',(-2.0000000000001,-15.,9.02890625));
#1592=CARTESIAN_POINT('',(-2.0000000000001,-15.,8.83046875));
#1593=CARTESIAN_POINT('',(-2.0000000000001,-15.,8.73125));
#1594=CARTESIAN_POINT('',(-2.0000000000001,-15.,8.5328125));
#1595=CARTESIAN_POINT('',(-2.0000000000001,-15.,8.43359375));
#1596=CARTESIAN_POINT('',(-2.0000000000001,-15.,8.23515625));
#1597=CARTESIAN_POINT('',(-2.0000000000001,-15.,8.1359375));
#1598=CARTESIAN_POINT('',(-2.0000000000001,-15.,7.9375));
#1599=CARTESIAN_POINT('',(-2.0000000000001,-15.,7.83828125));
#1600=CARTESIAN_POINT('',(-2.0000000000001,-15.,7.63984375));
#1601=CARTESIAN_POINT('',(-2.0000000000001,-15.,7.540625));
#1602=CARTESIAN_POINT('',(-2.0000000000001,-15.,7.3421875));
#1603=CARTESIAN_POINT('',(-2.0000000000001,-15.,7.24296875));
#1604=CARTESIAN_POINT('',(-2.0000000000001,-15.,7.04453125));
#1605=CARTESIAN_POINT('',(-2.0000000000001,-15.,6.9453125));
#1606=CARTESIAN_POINT('',(-2.0000000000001,-15.,6.746875));
#1607=CARTESIAN_POINT('',(-2.0000000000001,-15.,6.64765625));
#1608=CARTESIAN_POINT('',(-2.0000000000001,-15.,6.44921875));
#1609=CARTESIAN_POINT('',(-2.0000000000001,-15.,6.35));
#1610=CARTESIAN_POINT('',(-2.0000000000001,-15.,6.1515625));
#1611=CARTESIAN_POINT('',(-2.0000000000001,-15.,6.05234375));
#1612=CARTESIAN_POINT('',(-2.0000000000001,-15.,5.85390625));
#1613=CARTESIAN_POINT('',(-2.0000000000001,-15.,5.7546875));
#1614=CARTESIAN_POINT('',(-2.0000000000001,-15.,5.55625));
#1615=CARTESIAN_POINT('',(-2.0000000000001,-15.,5.45703125));
#1616=CARTESIAN_POINT('',(-2.0000000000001,-15.,5.25859375));
#1617=CARTESIAN_POINT('',(-2.0000000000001,-15.,5.159375));
#1618=CARTESIAN_POINT('',(-2.0000000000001,-15.,4.9609375));
#1619=CARTESIAN_POINT('',(-2.0000000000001,-15.,4.86171875));
#1620=CARTESIAN_POINT('',(-2.0000000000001,-15.,4.66328125));
#1621=CARTESIAN_POINT('',(-2.0000000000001,-15.,4.5640625));
#1622=CARTESIAN_POINT('',(-2.0000000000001,-15.,4.365625));
#1623=CARTESIAN_POINT('',(-2.0000000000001,-15.,4.26640625));
#1624=CARTESIAN_POINT('',(-2.0000000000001,-15.,4.06796875));
#1625=CARTESIAN_POINT('',(-2.0000000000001,-15.,3.96875));
#1626=CARTESIAN_POINT('',(-2.0000000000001,-15.,3.7703125));
#1627=CARTESIAN_POINT('',(-2.0000000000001,-15.,3.67109375));
#1628=CARTESIAN_POINT('',(-2.0000000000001,-15.,3.47265625));
#1629=CARTESIAN_POINT('',(-2.0000000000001,-15.,3.3734375));
#1630=CARTESIAN_POINT('',(-2.0000000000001,-15.,3.175));
#1631=CARTESIAN_POINT('',(-2.0000000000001,-15.,3.07578125));
#1632=CARTESIAN_POINT('',(-2.0000000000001,-15.,2.87734375));
#1633=CARTESIAN_POINT('',(-2.0000000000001,-15.,2.778125));
#1634=CARTESIAN_POINT('',(-2.0000000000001,-15.,2.5796875));
#1635=CARTESIAN_POINT('',(-2.0000000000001,-15.,2.48046875));
#1636=CARTESIAN_POINT('',(-2.0000000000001,-15.,2.28203125));
#1637=CARTESIAN_POINT('',(-2.0000000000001,-15.,2.1828125));
#1638=CARTESIAN_POINT('',(-2.0000000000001,-15.,1.984375));
#1639=CARTESIAN_POINT('',(-2.0000000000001,-15.,1.88515625));
#1640=CARTESIAN_POINT('',(-2.0000000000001,-15.,1.68671875));
#1641=CARTESIAN_POINT('',(-2.0000000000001,-15.,1.5875));
#1642=CARTESIAN_POINT('',(-2.0000000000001,-15.,1.3890625));
#1643=CARTESIAN_POINT('',(-2.0000000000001,-15.,1.28984375));
#1644=CARTESIAN_POINT('',(-2.0000000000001,-15.,1.09140625));
#1645=CARTESIAN_POINT('',(-2.0000000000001,-15.,0.992187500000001));
#1646=CARTESIAN_POINT('',(-2.0000000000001,-15.,0.793750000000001));
#1647=CARTESIAN_POINT('',(-2.0000000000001,-15.,0.69453125));
#1648=CARTESIAN_POINT('',(-2.0000000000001,-15.,0.49609375));
#1649=CARTESIAN_POINT('',(-2.0000000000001,-15.,0.396875));
#1650=CARTESIAN_POINT('',(-2.0000000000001,-15.,0.1984375));
#1651=CARTESIAN_POINT('',(-2.0000000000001,-15.,0.0992187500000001));
#1652=CARTESIAN_POINT('',(-2.0000000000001,-15.,0.));
#1653=B_SPLINE_CURVE_WITH_KNOTS('',3,(#1587,#1588,#1589,#1590,#1591,#1592,#1593,#1594,#1595,
#1596,#1597,#1598,#1599,#1600,#1601,#1602,#1603,#1604,#1605,#1606,#1607,#1608,#1609,#1610,#1611,
#1612,#1613,#1614,#1615,#1616,#1617,#1618,#1619,#1620,#1621,#1622,#1623,#1624,#1625,#1626,#1627,
#1628,#1629,#1630,#1631,#1632,#1633,#1634,#1635,#1636,#1637,#1638,#1639,#1640,#1641,#1642,#1643,
#1644,#1645,#1646,#1647,#1648,#1649,#1650,#1651,#1652),.UNSPECIFIED.,.F.,.F.,(4,2,2,2,2,2,2,2,2,
2,2,2,2,2,2,2,2,2,2,2,2,2,2,2,2,2,2,2,2,2,2,2,4),(0.,0.297656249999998,0.595312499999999,
0.892968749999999,1.190625,1.48828125,1.7859375,2.08359375,2.38125,2.67890625,2.9765625,
3.27421875,3.571875,3.86953125,4.1671875,4.46484375,4.7625,5.06015625,5.3578125,5.65546875,
5.953125,6.25078125,6.5484375,6.84609375,7.14375,7.44140625,7.7390625,8.03671875,8.334375,
8.63203125,8.9296875,9.22734375,9.525),.UNSPECIFIED.);
#1654=EDGE_CURVE('BSEAM464',#231,#438,#1653,.T.);
#1655=ORIENTED_EDGE('',*,*,#232,.T.);
#1656=ORIENTED_EDGE('',*,*,#439,.F.);
#1657=ORIENTED_EDGE('',*,*,#1654,.T.);
#1658=ORIENTED_EDGE('',*,*,#1654,.F.);
#1659=EDGE_LOOP('',(#1655,#1657,#1656,#1658));
#1660=FACE_BOUND('',#1659,.T.);
#1661=ADVANCED_FACE('F464',(#1660),#1586,.F.);
#1662=CARTESIAN_POINT('',(-12.9903810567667,-7.49999999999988,9.525));
#1663=DIRECTION('',(0.,0.,-1.));
#1664=DIRECTION('',(-1.,0.,0.));
#1665=AXIS2_PLACEMENT_3D('',#1662,#1663,#1664);
#1666=CYLINDRICAL_SURFACE('',#1665,2.);
#1667=CARTESIAN_POINT('',(-14.9903810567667,-7.49999999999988,9.525));
#1668=CARTESIAN_POINT('',(-14.9903810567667,-7.49999999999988,9.42578125));
#1669=CARTESIAN_POINT('',(-14.9903810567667,-7.49999999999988,9.3265625));
#1670=CARTESIAN_POINT('',(-14.9903810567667,-7.49999999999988,9.128125));
#1671=CARTESIAN_POINT('',(-14.9903810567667,-7.49999999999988,9.02890625));
#1672=CARTESIAN_POINT('',(-14.9903810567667,-7.49999999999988,8.83046875));
#1673=CARTESIAN_POINT('',(-14.9903810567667,-7.49999999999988,8.73125));
#1674=CARTESIAN_POINT('',(-14.9903810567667,-7.49999999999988,8.5328125));
#1675=CARTESIAN_POINT('',(-14.9903810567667,-7.49999999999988,8.43359375));
#1676=CARTESIAN_POINT('',(-14.9903810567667,-7.49999999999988,8.23515625));
#1677=CARTESIAN_POINT('',(-14.9903810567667,-7.49999999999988,8.1359375));
#1678=CARTESIAN_POINT('',(-14.9903810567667,-7.49999999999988,7.9375));
#1679=CARTESIAN_POINT('',(-14.9903810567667,-7.49999999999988,7.83828125));
#1680=CARTESIAN_POINT('',(-14.9903810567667,-7.49999999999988,7.63984375));
#1681=CARTESIAN_POINT('',(-14.9903810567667,-7.49999999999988,7.540625));
#1682=CARTESIAN_POINT('',(-14.9903810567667,-7.49999999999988,7.3421875));
#1683=CARTESIAN_POINT('',(-14.9903810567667,-7.49999999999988,7.24296875));
#1684=CARTESIAN_POINT('',(-14.9903810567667,-7.49999999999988,7.04453125));
#1685=CARTESIAN_POINT('',(-14.9903810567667,-7.49999999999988,6.9453125));
#1686=CARTESIAN_POINT('',(-14.9903810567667,-7.49999999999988,6.746875));
#1687=CARTESIAN_POINT('',(-14.9903810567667,-7.49999999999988,6.64765625));
#1688=CARTESIAN_POINT('',(-14.9903810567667,-7.49999999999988,6.44921875));
#1689=CARTESIAN_POINT('',(-14.9903810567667,-7.49999999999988,6.35));
#1690=CARTESIAN_POINT('',(-14.9903810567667,-7.49999999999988,6.1515625));
#1691=CARTESIAN_POINT('',(-14.9903810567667,-7.49999999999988,6.05234375));
#1692=CARTESIAN_POINT('',(-14.9903810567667,-7.49999999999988,5.85390625));
#1693=CARTESIAN_POINT('',(-14.9903810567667,-7.49999999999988,5.7546875));
#1694=CARTESIAN_POINT('',(-14.9903810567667,-7.49999999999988,5.55625));
#1695=CARTESIAN_POINT('',(-14.9903810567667,-7.49999999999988,5.45703125));
#1696=CARTESIAN_POINT('',(-14.9903810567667,-7.49999999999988,5.25859375));
#1697=CARTESIAN_POINT('',(-14.9903810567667,-7.49999999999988,5.159375));
#1698=CARTESIAN_POINT('',(-14.9903810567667,-7.49999999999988,4.9609375));
#1699=CARTESIAN_POINT('',(-14.9903810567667,-7.49999999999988,4.86171875));
#1700=CARTESIAN_POINT('',(-14.9903810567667,-7.49999999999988,4.66328125));
#1701=CARTESIAN_POINT('',(-14.9903810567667,-7.49999999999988,4.5640625));
#1702=CARTESIAN_POINT('',(-14.9903810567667,-7.49999999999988,4.365625));
#1703=CARTESIAN_POINT('',(-14.9903810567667,-7.49999999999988,4.26640625));
#1704=CARTESIAN_POINT('',(-14.9903810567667,-7.49999999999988,4.06796875));
#1705=CARTESIAN_POINT('',(-14.9903810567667,-7.49999999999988,3.96875));
#1706=CARTESIAN_POINT('',(-14.9903810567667,-7.49999999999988,3.7703125));
#1707=CARTESIAN_POINT('',(-14.9903810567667,-7.49999999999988,3.67109375));
#1708=CARTESIAN_POINT('',(-14.9903810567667,-7.49999999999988,3.47265625));
#1709=CARTESIAN_POINT('',(-14.9903810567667,-7.49999999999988,3.3734375));
#1710=CARTESIAN_POINT('',(-14.9903810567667,-7.49999999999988,3.175));
#1711=CARTESIAN_POINT('',(-14.9903810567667,-7.49999999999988,3.07578125));
#1712=CARTESIAN_POINT('',(-14.9903810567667,-7.49999999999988,2.87734375));
#1713=CARTESIAN_POINT('',(-14.9903810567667,-7.49999999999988,2.778125));
#1714=CARTESIAN_POINT('',(-14.9903810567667,-7.49999999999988,2.5796875));
#1715=CARTESIAN_POINT('',(-14.9903810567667,-7.49999999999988,2.48046875));
#1716=CARTESIAN_POINT('',(-14.9903810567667,-7.49999999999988,2.28203125));
#1717=CARTESIAN_POINT('',(-14.9903810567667,-7.49999999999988,2.1828125));
#1718=CARTESIAN_POINT('',(-14.9903810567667,-7.49999999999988,1.984375));
#1719=CARTESIAN_POINT('',(-14.9903810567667,-7.49999999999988,1.88515625));
#1720=CARTESIAN_POINT('',(-14.9903810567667,-7.49999999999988,1.68671875));
#1721=CARTESIAN_POINT('',(-14.9903810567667,-7.49999999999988,1.5875));
#1722=CARTESIAN_POINT('',(-14.9903810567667,-7.49999999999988,1.3890625));
#1723=CARTESIAN_POINT('',(-14.9903810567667,-7.49999999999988,1.28984375));
#1724=CARTESIAN_POINT('',(-14.9903810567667,-7.49999999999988,1.09140625));
#1725=CARTESIAN_POINT('',(-14.9903810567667,-7.49999999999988,0.992187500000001));
#1726=CARTESIAN_POINT('',(-14.9903810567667,-7.49999999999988,0.793750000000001));
#1727=CARTESIAN_POINT('',(-14.9903810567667,-7.49999999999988,0.69453125));
#1728=CARTESIAN_POINT('',(-14.9903810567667,-7.49999999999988,0.49609375));
#1729=CARTESIAN_POINT('',(-14.9903810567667,-7.49999999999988,0.396875));
#1730=CARTESIAN_POINT('',(-14.9903810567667,-7.49999999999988,0.1984375));
#1731=CARTESIAN_POINT('',(-14.9903810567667,-7.49999999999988,0.0992187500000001));
#1732=CARTESIAN_POINT('',(-14.9903810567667,-7.49999999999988,0.));
#1733=B_SPLINE_CURVE_WITH_KNOTS('',3,(#1667,#1668,#1669,#1670,#1671,#1672,#1673,#1674,#1675,
#1676,#1677,#1678,#1679,#1680,#1681,#1682,#1683,#1684,#1685,#1686,#1687,#1688,#1689,#1690,#1691,
#1692,#1693,#1694,#1695,#1696,#1697,#1698,#1699,#1700,#1701,#1702,#1703,#1704,#1705,#1706,#1707,
#1708,#1709,#1710,#1711,#1712,#1713,#1714,#1715,#1716,#1717,#1718,#1719,#1720,#1721,#1722,#1723,
#1724,#1725,#1726,#1727,#1728,#1729,#1730,#1731,#1732),.UNSPECIFIED.,.F.,.F.,(4,2,2,2,2,2,2,2,2,
2,2,2,2,2,2,2,2,2,2,2,2,2,2,2,2,2,2,2,2,2,2,2,4),(0.,0.297656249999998,0.595312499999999,
0.892968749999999,1.190625,1.48828125,1.7859375,2.08359375,2.38125,2.67890625,2.9765625,
3.27421875,3.571875,3.86953125,4.1671875,4.46484375,4.7625,5.06015625,5.3578125,5.65546875,
5.953125,6.25078125,6.5484375,6.84609375,7.14375,7.44140625,7.7390625,8.03671875,8.334375,
8.63203125,8.9296875,9.22734375,9.525),.UNSPECIFIED.);
#1734=EDGE_CURVE('BSEAM472',#41,#449,#1733,.T.);
#1735=ORIENTED_EDGE('',*,*,#42,.T.);
#1736=ORIENTED_EDGE('',*,*,#450,.F.);
#1737=ORIENTED_EDGE('',*,*,#1734,.T.);
#1738=ORIENTED_EDGE('',*,*,#1734,.F.);
#1739=EDGE_LOOP('',(#1735,#1737,#1736,#1738));
#1740=FACE_BOUND('',#1739,.T.);
#1741=ADVANCED_FACE('F472',(#1740),#1666,.F.);
#1742=CARTESIAN_POINT('',(-12.9903810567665,7.50000000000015,9.525));
#1743=DIRECTION('',(0.,0.,-1.));
#1744=DIRECTION('',(-1.,0.,0.));
#1745=AXIS2_PLACEMENT_3D('',#1742,#1743,#1744);
#1746=CYLINDRICAL_SURFACE('',#1745,2.);
#1747=CARTESIAN_POINT('',(-14.9903810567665,7.50000000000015,9.525));
#1748=CARTESIAN_POINT('',(-14.9903810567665,7.50000000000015,9.42578125));
#1749=CARTESIAN_POINT('',(-14.9903810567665,7.50000000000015,9.3265625));
#1750=CARTESIAN_POINT('',(-14.9903810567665,7.50000000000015,9.128125));
#1751=CARTESIAN_POINT('',(-14.9903810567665,7.50000000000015,9.02890625));
#1752=CARTESIAN_POINT('',(-14.9903810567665,7.50000000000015,8.83046875));
#1753=CARTESIAN_POINT('',(-14.9903810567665,7.50000000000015,8.73125));
#1754=CARTESIAN_POINT('',(-14.9903810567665,7.50000000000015,8.5328125));
#1755=CARTESIAN_POINT('',(-14.9903810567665,7.50000000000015,8.43359375));
#1756=CARTESIAN_POINT('',(-14.9903810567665,7.50000000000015,8.23515625));
#1757=CARTESIAN_POINT('',(-14.9903810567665,7.50000000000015,8.1359375));
#1758=CARTESIAN_POINT('',(-14.9903810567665,7.50000000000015,7.9375));
#1759=CARTESIAN_POINT('',(-14.9903810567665,7.50000000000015,7.83828125));
#1760=CARTESIAN_POINT('',(-14.9903810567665,7.50000000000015,7.63984375));
#1761=CARTESIAN_POINT('',(-14.9903810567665,7.50000000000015,7.540625));
#1762=CARTESIAN_POINT('',(-14.9903810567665,7.50000000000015,7.3421875));
#1763=CARTESIAN_POINT('',(-14.9903810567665,7.50000000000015,7.24296875));
#1764=CARTESIAN_POINT('',(-14.9903810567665,7.50000000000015,7.04453125));
#1765=CARTESIAN_POINT('',(-14.9903810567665,7.50000000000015,6.9453125));
#1766=CARTESIAN_POINT('',(-14.9903810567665,7.50000000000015,6.746875));
#1767=CARTESIAN_POINT('',(-14.9903810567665,7.50000000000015,6.64765625));
#1768=CARTESIAN_POINT('',(-14.9903810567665,7.50000000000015,6.44921875));
#1769=CARTESIAN_POINT('',(-14.9903810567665,7.50000000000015,6.35));
#1770=CARTESIAN_POINT('',(-14.9903810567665,7.50000000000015,6.1515625));
#1771=CARTESIAN_POINT('',(-14.9903810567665,7.50000000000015,6.05234375));
#1772=CARTESIAN_POINT('',(-14.9903810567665,7.50000000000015,5.85390625));
#1773=CARTESIAN_POINT('',(-14.9903810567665,7.50000000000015,5.7546875));
#1774=CARTESIAN_POINT('',(-14.9903810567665,7.50000000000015,5.55625));
#1775=CARTESIAN_POINT('',(-14.9903810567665,7.50000000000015,5.45703125));
#1776=CARTESIAN_POINT('',(-14.9903810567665,7.50000000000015,5.25859375));
#1777=CARTESIAN_POINT('',(-14.9903810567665,7.50000000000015,5.159375));
#1778=CARTESIAN_POINT('',(-14.9903810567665,7.50000000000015,4.9609375));
#1779=CARTESIAN_POINT('',(-14.9903810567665,7.50000000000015,4.86171875));
#1780=CARTESIAN_POINT('',(-14.9903810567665,7.50000000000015,4.66328125));
#1781=CARTESIAN_POINT('',(-14.9903810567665,7.50000000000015,4.5640625));
#1782=CARTESIAN_POINT('',(-14.9903810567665,7.50000000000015,4.365625));
#1783=CARTESIAN_POINT('',(-14.9903810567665,7.50000000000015,4.26640625));
#1784=CARTESIAN_POINT('',(-14.9903810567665,7.50000000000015,4.06796875));
#1785=CARTESIAN_POINT('',(-14.9903810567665,7.50000000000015,3.96875));
#1786=CARTESIAN_POINT('',(-14.9903810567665,7.50000000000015,3.7703125));
#1787=CARTESIAN_POINT('',(-14.9903810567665,7.50000000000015,3.67109375));
#1788=CARTESIAN_POINT('',(-14.9903810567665,7.50000000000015,3.47265625));
#1789=CARTESIAN_POINT('',(-14.9903810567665,7.50000000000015,3.3734375));
#1790=CARTESIAN_POINT('',(-14.9903810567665,7.50000000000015,3.175));
#1791=CARTESIAN_POINT('',(-14.9903810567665,7.50000000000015,3.07578125));
#1792=CARTESIAN_POINT('',(-14.9903810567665,7.50000000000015,2.87734375));
#1793=CARTESIAN_POINT('',(-14.9903810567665,7.50000000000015,2.778125));
#1794=CARTESIAN_POINT('',(-14.9903810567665,7.50000000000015,2.5796875));
#1795=CARTESIAN_POINT('',(-14.9903810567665,7.50000000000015,2.48046875));
#1796=CARTESIAN_POINT('',(-14.9903810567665,7.50000000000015,2.28203125));
#1797=CARTESIAN_POINT('',(-14.9903810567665,7.50000000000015,2.1828125));
#1798=CARTESIAN_POINT('',(-14.9903810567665,7.50000000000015,1.984375));
#1799=CARTESIAN_POINT('',(-14.9903810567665,7.50000000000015,1.88515625));
#1800=CARTESIAN_POINT('',(-14.9903810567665,7.50000000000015,1.68671875));
#1801=CARTESIAN_POINT('',(-14.9903810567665,7.50000000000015,1.5875));
#1802=CARTESIAN_POINT('',(-14.9903810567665,7.50000000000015,1.3890625));
#1803=CARTESIAN_POINT('',(-14.9903810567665,7.50000000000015,1.28984375));
#1804=CARTESIAN_POINT('',(-14.9903810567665,7.50000000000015,1.09140625));
#1805=CARTESIAN_POINT('',(-14.9903810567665,7.50000000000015,0.992187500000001));
#1806=CARTESIAN_POINT('',(-14.9903810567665,7.50000000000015,0.793750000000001));
#1807=CARTESIAN_POINT('',(-14.9903810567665,7.50000000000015,0.69453125));
#1808=CARTESIAN_POINT('',(-14.9903810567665,7.50000000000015,0.49609375));
#1809=CARTESIAN_POINT('',(-14.9903810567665,7.50000000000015,0.396875));
#1810=CARTESIAN_POINT('',(-14.9903810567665,7.50000000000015,0.1984375));
#1811=CARTESIAN_POINT('',(-14.9903810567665,7.50000000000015,0.0992187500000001));
#1812=CARTESIAN_POINT('',(-14.9903810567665,7.50000000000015,0.));
#1813=B_SPLINE_CURVE_WITH_KNOTS('',3,(#1747,#1748,#1749,#1750,#1751,#1752,#1753,#1754,#1755,
#1756,#1757,#1758,#1759,#1760,#1761,#1762,#1763,#1764,#1765,#1766,#1767,#1768,#1769,#1770,#1771,
#1772,#1773,#1774,#1775,#1776,#1777,#1778,#1779,#1780,#1781,#1782,#1783,#1784,#1785,#1786,#1787,
#1788,#1789,#1790,#1791,#1792,#1793,#1794,#1795,#1796,#1797,#1798,#1799,#1800,#1801,#1802,#1803,
#1804,#1805,#1806,#1807,#1808,#1809,#1810,#1811,#1812),.UNSPECIFIED.,.F.,.F.,(4,2,2,2,2,2,2,2,2,
2,2,2,2,2,2,2,2,2,2,2,2,2,2,2,2,2,2,2,2,2,2,2,4),(0.,0.297656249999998,0.595312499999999,
0.892968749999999,1.190625,1.48828125,1.7859375,2.08359375,2.38125,2.67890625,2.9765625,
3.27421875,3.571875,3.86953125,4.1671875,4.46484375,4.7625,5.06015625,5.3578125,5.65546875,
5.953125,6.25078125,6.5484375,6.84609375,7.14375,7.44140625,7.7390625,8.03671875,8.334375,
8.63203125,8.9296875,9.22734375,9.525),.UNSPECIFIED.);
#1814=EDGE_CURVE('BSEAM146',#242,#460,#1813,.T.);
#1815=ORIENTED_EDGE('',*,*,#243,.T.);
#1816=ORIENTED_EDGE('',*,*,#461,.F.);
#1817=ORIENTED_EDGE('',*,*,#1814,.T.);
#1818=ORIENTED_EDGE('',*,*,#1814,.F.);
#1819=EDGE_LOOP('',(#1815,#1817,#1816,#1818));
#1820=FACE_BOUND('',#1819,.T.);
#1821=ADVANCED_FACE('F146',(#1820),#1746,.F.);
#1822=CARTESIAN_POINT('',(14.25,-1.50920942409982E-13,9.525));
#1823=DIRECTION('',(0.,0.,-1.));
#1824=DIRECTION('',(-1.,0.,0.));
#1825=AXIS2_PLACEMENT_3D('',#1822,#1823,#1824);
#1826=CYLINDRICAL_SURFACE('',#1825,3.);
#1827=CARTESIAN_POINT('',(14.25,-1.50920942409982E-13,5.525));
#1828=DIRECTION('',(0.,0.,1.));
#1829=DIRECTION('',(1.,0.,0.));
#1830=AXIS2_PLACEMENT_3D('',#1827,#1828,#1829);
#1831=CIRCLE('',#1830,3.);
#1832=CARTESIAN_POINT('',(11.25,-1.50920942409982E-13,5.525));
#1833=VERTEX_POINT('',#1832);
#1834=EDGE_CURVE('E54',#1833,#1833,#1831,.T.);
#1835=CARTESIAN_POINT('',(11.25,-1.50920942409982E-13,5.525));
#1836=CARTESIAN_POINT('',(11.25,-1.50920942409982E-13,5.56666666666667));
#1837=CARTESIAN_POINT('',(11.25,-1.50920942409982E-13,5.60833333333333));
#1838=CARTESIAN_POINT('',(11.25,-1.50920942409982E-13,5.69166666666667));
#1839=CARTESIAN_POINT('',(11.25,-1.50920942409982E-13,5.73333333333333));
#1840=CARTESIAN_POINT('',(11.25,-1.50920942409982E-13,5.81666666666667));
#1841=CARTESIAN_POINT('',(11.25,-1.50920942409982E-13,5.85833333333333));
#1842=CARTESIAN_POINT('',(11.25,-1.50920942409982E-13,5.94166666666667));
#1843=CARTESIAN_POINT('',(11.25,-1.50920942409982E-13,5.98333333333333));
#1844=CARTESIAN_POINT('',(11.25,-1.50920942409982E-13,6.06666666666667));
#1845=CARTESIAN_POINT('',(11.25,-1.50920942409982E-13,6.10833333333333));
#1846=CARTESIAN_POINT('',(11.25,-1.50920942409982E-13,6.19166666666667));
#1847=CARTESIAN_POINT('',(11.25,-1.50920942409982E-13,6.23333333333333));
#1848=CARTESIAN_POINT('',(11.25,-1.50920942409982E-13,6.31666666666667));
#1849=CARTESIAN_POINT('',(11.25,-1.50920942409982E-13,6.35833333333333));
#1850=CARTESIAN_POINT('',(11.25,-1.50920942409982E-13,6.44166666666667));
#1851=CARTESIAN_POINT('',(11.25,-1.50920942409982E-13,6.48333333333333));
#1852=CARTESIAN_POINT('',(11.25,-1.50920942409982E-13,6.56666666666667));
#1853=CARTESIAN_POINT('',(11.25,-1.50920942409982E-13,6.60833333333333));
#1854=CARTESIAN_POINT('',(11.25,-1.50920942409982E-13,6.69166666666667));
#1855=CARTESIAN_POINT('',(11.25,-1.50920942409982E-13,6.73333333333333));
#1856=CARTESIAN_POINT('',(11.25,-1.50920942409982E-13,6.81666666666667));
#1857=CARTESIAN_POINT('',(11.25,-1.50920942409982E-13,6.85833333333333));
#1858=CARTESIAN_POINT('',(11.25,-1.50920942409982E-13,6.94166666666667));
#1859=CARTESIAN_POINT('',(11.25,-1.50920942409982E-13,6.98333333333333));
#1860=CARTESIAN_POINT('',(11.25,-1.50920942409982E-13,7.06666666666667));
#1861=CARTESIAN_POINT('',(11.25,-1.50920942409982E-13,7.10833333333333));
#1862=CARTESIAN_POINT('',(11.25,-1.50920942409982E-13,7.19166666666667));
#1863=CARTESIAN_POINT('',(11.25,-1.50920942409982E-13,7.23333333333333));
#1864=CARTESIAN_POINT('',(11.25,-1.50920942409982E-13,7.31666666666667));
#1865=CARTESIAN_POINT('',(11.25,-1.50920942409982E-13,7.35833333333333));
#1866=CARTESIAN_POINT('',(11.25,-1.50920942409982E-13,7.44166666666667));
#1867=CARTESIAN_POINT('',(11.25,-1.50920942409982E-13,7.48333333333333));
#1868=CARTESIAN_POINT('',(11.25,-1.50920942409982E-13,7.56666666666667));
#1869=CARTESIAN_POINT('',(11.25,-1.50920942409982E-13,7.60833333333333));
#1870=CARTESIAN_POINT('',(11.25,-1.50920942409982E-13,7.69166666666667));
#1871=CARTESIAN_POINT('',(11.25,-1.50920942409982E-13,7.73333333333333));
#1872=CARTESIAN_POINT('',(11.25,-1.50920942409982E-13,7.81666666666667));
#1873=CARTESIAN_POINT('',(11.25,-1.50920942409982E-13,7.85833333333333));
#1874=CARTESIAN_POINT('',(11.25,-1.50920942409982E-13,7.94166666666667));
#1875=CARTESIAN_POINT('',(11.25,-1.50920942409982E-13,7.98333333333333));
#1876=CARTESIAN_POINT('',(11.25,-1.50920942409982E-13,8.06666666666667));
#1877=CARTESIAN_POINT('',(11.25,-1.50920942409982E-13,8.10833333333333));
#1878=CARTESIAN_POINT('',(11.25,-1.50920942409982E-13,8.19166666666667));
#1879=CARTESIAN_POINT('',(11.25,-1.50920942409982E-13,8.23333333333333));
#1880=CARTESIAN_POINT('',(11.25,-1.50920942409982E-13,8.31666666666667));
#1881=CARTESIAN_POINT('',(11.25,-1.50920942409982E-13,8.35833333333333));
#1882=CARTESIAN_POINT('',(11.25,-1.50920942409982E-13,8.44166666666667));
#1883=CARTESIAN_POINT('',(11.25,-1.50920942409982E-13,8.48333333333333));
#1884=CARTESIAN_POINT('',(11.25,-1.50920942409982E-13,8.56666666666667));
#1885=CARTESIAN_POINT('',(11.25,-1.50920942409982E-13,8.60833333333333));
#1886=CARTESIAN_POINT('',(11.25,-1.50920942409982E-13,8.69166666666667));
#1887=CARTESIAN_POINT('',(11.25,-1.50920942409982E-13,8.73333333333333));
#1888=CARTESIAN_POINT('',(11.25,-1.50920942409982E-13,8.81666666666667));
#1889=CARTESIAN_POINT('',(11.25,-1.50920942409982E-13,8.85833333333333));
#1890=CARTESIAN_POINT('',(11.25,-1.50920942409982E-13,8.94166666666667));
#1891=CARTESIAN_POINT('',(11.25,-1.50920942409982E-13,8.98333333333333));
#1892=CARTESIAN_POINT('',(11.25,-1.50920942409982E-13,9.06666666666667));
#1893=CARTESIAN_POINT('',(11.25,-1.50920942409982E-13,9.10833333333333));
#1894=CARTESIAN_POINT('',(11.25,-1.50920942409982E-13,9.19166666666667));
#1895=CARTESIAN_POINT('',(11.25,-1.50920942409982E-13,9.23333333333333));
#1896=CARTESIAN_POINT('',(11.25,-1.50920942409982E-13,9.31666666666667));
#1897=CARTESIAN_POINT('',(11.25,-1.50920942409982E-13,9.35833333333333));
#1898=CARTESIAN_POINT('',(11.25,-1.50920942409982E-13,9.44166666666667));
#1899=CARTESIAN_POINT('',(11.25,-1.50920942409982E-13,9.48333333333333));
#1900=CARTESIAN_POINT('',(11.25,-1.50920942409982E-13,9.525));
#1901=B_SPLINE_CURVE_WITH_KNOTS('',3,(#1835,#1836,#1837,#1838,#1839,#1840,#1841,#1842,#1843,
#1844,#1845,#1846,#1847,#1848,#1849,#1850,#1851,#1852,#1853,#1854,#1855,#1856,#1857,#1858,#1859,
#1860,#1861,#1862,#1863,#1864,#1865,#1866,#1867,#1868,#1869,#1870,#1871,#1872,#1873,#1874,#1875,
#1876,#1877,#1878,#1879,#1880,#1881,#1882,#1883,#1884,#1885,#1886,#1887,#1888,#1889,#1890,#1891,
#1892,#1893,#1894,#1895,#1896,#1897,#1898,#1899,#1900),.UNSPECIFIED.,.F.,.F.,(4,2,2,2,2,2,2,2,2,
2,2,2,2,2,2,2,2,2,2,2,2,2,2,2,2,2,2,2,2,2,2,2,4),(0.,0.124999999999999,0.249999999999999,
0.374999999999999,0.5,0.625,0.75,0.875,1.,1.125,1.25,1.375,1.5,1.625,1.75,1.875,2.,2.125,2.25,
2.375,2.5,2.625,2.75,2.875,3.,3.125,3.25,3.375,3.5,3.625,3.75,3.875,4.),.UNSPECIFIED.);
#1902=EDGE_CURVE('BSEAM145',#1833,#30,#1901,.T.);
#1903=ORIENTED_EDGE('',*,*,#1834,.F.);
#1904=ORIENTED_EDGE('',*,*,#31,.T.);
#1905=ORIENTED_EDGE('',*,*,#1902,.T.);
#1906=ORIENTED_EDGE('',*,*,#1902,.F.);
#1907=EDGE_LOOP('',(#1903,#1905,#1904,#1906));
#1908=FACE_BOUND('',#1907,.T.);
#1909=ADVANCED_FACE('F145',(#1908),#1826,.F.);
#1910=CARTESIAN_POINT('',(-7.12500000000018,-12.3408620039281,9.525));
#1911=DIRECTION('',(0.,0.,-1.));
#1912=DIRECTION('',(-1.,0.,0.));
#1913=AXIS2_PLACEMENT_3D('',#1910,#1911,#1912);
#1914=CYLINDRICAL_SURFACE('',#1913,3.);
#1915=CARTESIAN_POINT('',(-7.12500000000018,-12.3408620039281,5.525));
#1916=DIRECTION('',(0.,0.,1.));
#1917=DIRECTION('',(1.,0.,0.));
#1918=AXIS2_PLACEMENT_3D('',#1915,#1916,#1917);
#1919=CIRCLE('',#1918,3.);
#1920=CARTESIAN_POINT('',(-10.1250000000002,-12.3408620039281,5.525));
#1921=VERTEX_POINT('',#1920);
#1922=EDGE_CURVE('E131',#1921,#1921,#1919,.T.);
#1923=CARTESIAN_POINT('',(-10.1250000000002,-12.3408620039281,5.525));
#1924=CARTESIAN_POINT('',(-10.1250000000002,-12.3408620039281,5.56666666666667));
#1925=CARTESIAN_POINT('',(-10.1250000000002,-12.3408620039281,5.60833333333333));
#1926=CARTESIAN_POINT('',(-10.1250000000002,-12.3408620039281,5.69166666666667));
#1927=CARTESIAN_POINT('',(-10.1250000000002,-12.3408620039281,5.73333333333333));
#1928=CARTESIAN_POINT('',(-10.1250000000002,-12.3408620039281,5.81666666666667));
#1929=CARTESIAN_POINT('',(-10.1250000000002,-12.3408620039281,5.85833333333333));
#1930=CARTESIAN_POINT('',(-10.1250000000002,-12.3408620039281,5.94166666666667));
#1931=CARTESIAN_POINT('',(-10.1250000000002,-12.3408620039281,5.98333333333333));
#1932=CARTESIAN_POINT('',(-10.1250000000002,-12.3408620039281,6.06666666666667));
#1933=CARTESIAN_POINT('',(-10.1250000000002,-12.3408620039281,6.10833333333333));
#1934=CARTESIAN_POINT('',(-10.1250000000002,-12.3408620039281,6.19166666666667));
#1935=CARTESIAN_POINT('',(-10.1250000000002,-12.3408620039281,6.23333333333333));
#1936=CARTESIAN_POINT('',(-10.1250000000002,-12.3408620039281,6.31666666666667));
#1937=CARTESIAN_POINT('',(-10.1250000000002,-12.3408620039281,6.35833333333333));
#1938=CARTESIAN_POINT('',(-10.1250000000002,-12.3408620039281,6.44166666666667));
#1939=CARTESIAN_POINT('',(-10.1250000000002,-12.3408620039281,6.48333333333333));
#1940=CARTESIAN_POINT('',(-10.1250000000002,-12.3408620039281,6.56666666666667));
#1941=CARTESIAN_POINT('',(-10.1250000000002,-12.3408620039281,6.60833333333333));
#1942=CARTESIAN_POINT('',(-10.1250000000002,-12.3408620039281,6.69166666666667));
#1943=CARTESIAN_POINT('',(-10.1250000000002,-12.3408620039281,6.73333333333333));
#1944=CARTESIAN_POINT('',(-10.1250000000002,-12.3408620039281,6.81666666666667));
#1945=CARTESIAN_POINT('',(-10.1250000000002,-12.3408620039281,6.85833333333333));
#1946=CARTESIAN_POINT('',(-10.1250000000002,-12.3408620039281,6.94166666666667));
#1947=CARTESIAN_POINT('',(-10.1250000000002,-12.3408620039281,6.98333333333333));
#1948=CARTESIAN_POINT('',(-10.1250000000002,-12.3408620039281,7.06666666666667));
#1949=CARTESIAN_POINT('',(-10.1250000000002,-12.3408620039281,7.10833333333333));
#1950=CARTESIAN_POINT('',(-10.1250000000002,-12.3408620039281,7.19166666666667));
#1951=CARTESIAN_POINT('',(-10.1250000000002,-12.3408620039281,7.23333333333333));
#1952=CARTESIAN_POINT('',(-10.1250000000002,-12.3408620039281,7.31666666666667));
#1953=CARTESIAN_POINT('',(-10.1250000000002,-12.3408620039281,7.35833333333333));
#1954=CARTESIAN_POINT('',(-10.1250000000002,-12.3408620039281,7.44166666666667));
#1955=CARTESIAN_POINT('',(-10.1250000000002,-12.3408620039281,7.48333333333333));
#1956=CARTESIAN_POINT('',(-10.1250000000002,-12.3408620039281,7.56666666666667));
#1957=CARTESIAN_POINT('',(-10.1250000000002,-12.3408620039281,7.60833333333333));
#1958=CARTESIAN_POINT('',(-10.1250000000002,-12.3408620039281,7.69166666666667));
#1959=CARTESIAN_POINT('',(-10.1250000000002,-12.3408620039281,7.73333333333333));
#1960=CARTESIAN_POINT('',(-10.1250000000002,-12.3408620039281,7.81666666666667));
#1961=CARTESIAN_POINT('',(-10.1250000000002,-12.3408620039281,7.85833333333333));
#1962=CARTESIAN_POINT('',(-10.1250000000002,-12.3408620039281,7.94166666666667));
#1963=CARTESIAN_POINT('',(-10.1250000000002,-12.3408620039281,7.98333333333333));
#1964=CARTESIAN_POINT('',(-10.1250000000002,-12.3408620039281,8.06666666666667));
#1965=CARTESIAN_POINT('',(-10.1250000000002,-12.3408620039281,8.10833333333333));
#1966=CARTESIAN_POINT('',(-10.1250000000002,-12.3408620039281,8.19166666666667));
#1967=CARTESIAN_POINT('',(-10.1250000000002,-12.3408620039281,8.23333333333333));
#1968=CARTESIAN_POINT('',(-10.1250000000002,-12.3408620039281,8.31666666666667));
#1969=CARTESIAN_POINT('',(-10.1250000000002,-12.3408620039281,8.35833333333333));
#1970=CARTESIAN_POINT('',(-10.1250000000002,-12.3408620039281,8.44166666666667));
#1971=CARTESIAN_POINT('',(-10.1250000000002,-12.3408620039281,8.48333333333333));
#1972=CARTESIAN_POINT('',(-10.1250000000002,-12.3408620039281,8.56666666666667));
#1973=CARTESIAN_POINT('',(-10.1250000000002,-12.3408620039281,8.60833333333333));
#1974=CARTESIAN_POINT('',(-10.1250000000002,-12.3408620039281,8.69166666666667));
#1975=CARTESIAN_POINT('',(-10.1250000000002,-12.3408620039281,8.73333333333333));
#1976=CARTESIAN_POINT('',(-10.1250000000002,-12.3408620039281,8.81666666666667));
#1977=CARTESIAN_POINT('',(-10.1250000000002,-12.3408620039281,8.85833333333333));
#1978=CARTESIAN_POINT('',(-10.1250000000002,-12.3408620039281,8.94166666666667));
#1979=CARTESIAN_POINT('',(-10.1250000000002,-12.3408620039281,8.98333333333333));
#1980=CARTESIAN_POINT('',(-10.1250000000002,-12.3408620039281,9.06666666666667));
#1981=CARTESIAN_POINT('',(-10.1250000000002,-12.3408620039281,9.10833333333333));
#1982=CARTESIAN_POINT('',(-10.1250000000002,-12.3408620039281,9.19166666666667));
#1983=CARTESIAN_POINT('',(-10.1250000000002,-12.3408620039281,9.23333333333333));
#1984=CARTESIAN_POINT('',(-10.1250000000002,-12.3408620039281,9.31666666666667));
#1985=CARTESIAN_POINT('',(-10.1250000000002,-12.3408620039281,9.35833333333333));
#1986=CARTESIAN_POINT('',(-10.1250000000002,-12.3408620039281,9.44166666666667));
#1987=CARTESIAN_POINT('',(-10.1250000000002,-12.3408620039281,9.48333333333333));
#1988=CARTESIAN_POINT('',(-10.1250000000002,-12.3408620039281,9.525));
#1989=B_SPLINE_CURVE_WITH_KNOTS('',3,(#1923,#1924,#1925,#1926,#1927,#1928,#1929,#1930,#1931,
#1932,#1933,#1934,#1935,#1936,#1937,#1938,#1939,#1940,#1941,#1942,#1943,#1944,#1945,#1946,#1947,
#1948,#1949,#1950,#1951,#1952,#1953,#1954,#1955,#1956,#1957,#1958,#1959,#1960,#1961,#1962,#1963,
#1964,#1965,#1966,#1967,#1968,#1969,#1970,#1971,#1972,#1973,#1974,#1975,#1976,#1977,#1978,#1979,
#1980,#1981,#1982,#1983,#1984,#1985,#1986,#1987,#1988),.UNSPECIFIED.,.F.,.F.,(4,2,2,2,2,2,2,2,2,
2,2,2,2,2,2,2,2,2,2,2,2,2,2,2,2,2,2,2,2,2,2,2,4),(0.,0.124999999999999,0.249999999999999,
0.374999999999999,0.5,0.625,0.75,0.875,1.,1.125,1.25,1.375,1.5,1.625,1.75,1.875,2.,2.125,2.25,
2.375,2.5,2.625,2.75,2.875,3.,3.125,3.25,3.375,3.5,3.625,3.75,3.875,4.),.UNSPECIFIED.);
#1990=EDGE_CURVE('BSEAM150',#1921,#253,#1989,.T.);
#1991=ORIENTED_EDGE('',*,*,#1922,.F.);
#1992=ORIENTED_EDGE('',*,*,#254,.T.);
#1993=ORIENTED_EDGE('',*,*,#1990,.T.);
#1994=ORIENTED_EDGE('',*,*,#1990,.F.);
#1995=EDGE_LOOP('',(#1991,#1993,#1992,#1994));
#1996=FACE_BOUND('',#1995,.T.);
#1997=ADVANCED_FACE('F150',(#1996),#1914,.F.);
#1998=CARTESIAN_POINT('',(-7.12500000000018,-12.3408620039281,5.525));
#1999=DIRECTION('',(0.,0.,1.));
#2000=DIRECTION('',(1.,0.,0.));
#2001=AXIS2_PLACEMENT_3D('',#1998,#1999,#2000);
#2002=PLANE('',#2001);
#2003=ORIENTED_EDGE('',*,*,#1922,.T.);
#2004=EDGE_LOOP('',(#2003));
#2005=FACE_BOUND('',#2004,.T.);
#2006=ADVANCED_FACE('F501',(#2005),#2002,.T.);
#2007=CARTESIAN_POINT('',(14.25,-1.50920942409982E-13,5.525));
#2008=DIRECTION('',(0.,0.,1.));
#2009=DIRECTION('',(1.,0.,0.));
#2010=AXIS2_PLACEMENT_3D('',#2007,#2008,#2009);
#2011=PLANE('',#2010);
#2012=ORIENTED_EDGE('',*,*,#1834,.T.);
#2013=EDGE_LOOP('',(#2012));
#2014=FACE_BOUND('',#2013,.T.);
#2015=ADVANCED_FACE('F142',(#2014),#2011,.T.);
#2016=CARTESIAN_POINT('',(-7.12499999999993,12.3408620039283,5.525));
#2017=DIRECTION('',(0.,0.,1.));
#2018=DIRECTION('',(1.,0.,0.));
#2019=AXIS2_PLACEMENT_3D('',#2016,#2017,#2018);
#2020=PLANE('',#2019);
#2021=ORIENTED_EDGE('',*,*,#1346,.T.);
#2022=EDGE_LOOP('',(#2021));
#2023=FACE_BOUND('',#2022,.T.);
#2024=ADVANCED_FACE('F534',(#2023),#2020,.T.);
#2025=CLOSED_SHELL('',(#258,#465,#487,#504,#521,#533,#613,#693,#773,#853,#933,#1013,#1093,#1173,
#1253,#1333,#1421,#1501,#1581,#1661,#1741,#1821,#1909,#1997,#2006,#2015,#2024));
#2026=MANIFOLD_SOLID_BREP('B2',#2025);
#2027=ADVANCED_BREP_SHAPE_REPRESENTATION('',(#18,#2026),#14);
#2028=SHAPE_DEFINITION_REPRESENTATION(#9,#2027);
ENDSEC;
END-ISO-10303-21;
